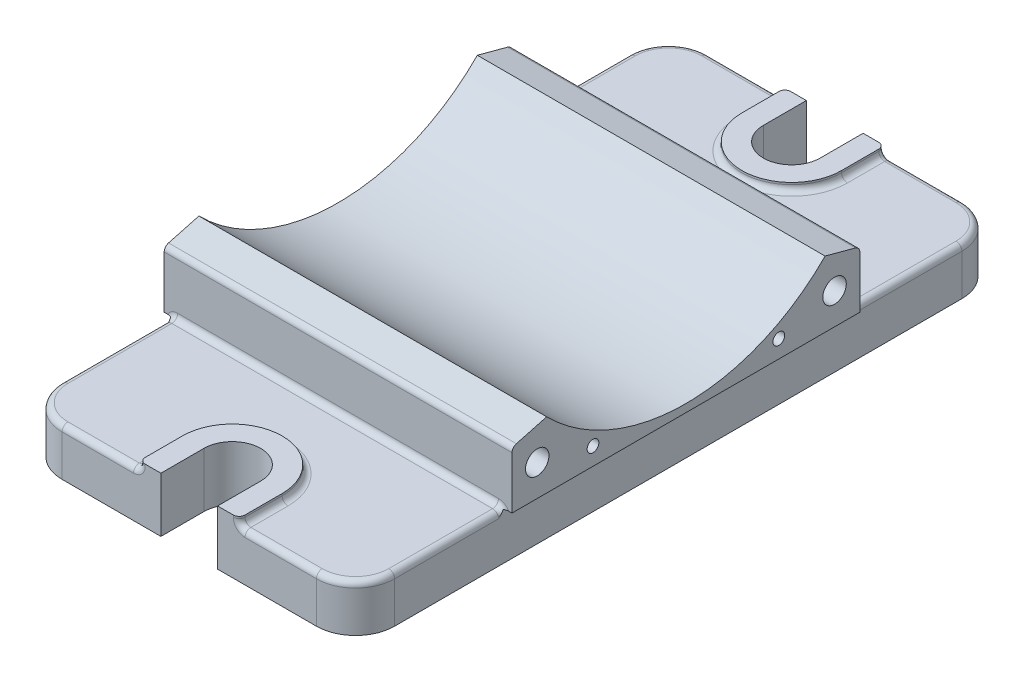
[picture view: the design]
ISO-10303-21;
HEADER;
FILE_DESCRIPTION(('STEP AP214'),'2;1');
FILE_NAME('part.step','',(''),(''),'','','');
FILE_SCHEMA(('AUTOMOTIVE_DESIGN { 1 0 10303 214 1 1 1 1 }'));
ENDSEC;
DATA;
#1=APPLICATION_CONTEXT('core data for automotive mechanical design processes');
#2=APPLICATION_PROTOCOL_DEFINITION('international standard','automotive_design',2000,#1);
#3=PRODUCT_CONTEXT('',#1,'mechanical');
#4=PRODUCT('Part','Part','',(#3));
#5=PRODUCT_RELATED_PRODUCT_CATEGORY('part','',(#4));
#6=PRODUCT_DEFINITION_FORMATION('','',#4);
#7=PRODUCT_DEFINITION_CONTEXT('part definition',#1,'design');
#8=PRODUCT_DEFINITION('design','',#6,#7);
#9=PRODUCT_DEFINITION_SHAPE('','',#8);
#10=(LENGTH_UNIT() NAMED_UNIT(*) SI_UNIT(.MILLI.,.METRE.));
#11=(NAMED_UNIT(*) PLANE_ANGLE_UNIT() SI_UNIT($,.RADIAN.));
#12=(NAMED_UNIT(*) SI_UNIT($,.STERADIAN.) SOLID_ANGLE_UNIT());
#13=UNCERTAINTY_MEASURE_WITH_UNIT(LENGTH_MEASURE(1.E-05),#10,'distance_accuracy_value','');
#14=(GEOMETRIC_REPRESENTATION_CONTEXT(3) GLOBAL_UNCERTAINTY_ASSIGNED_CONTEXT((#13)) GLOBAL_UNIT_ASSIGNED_CONTEXT((#10,
#11,#12)) REPRESENTATION_CONTEXT('',''));
#15=CARTESIAN_POINT('',(0.,0.,0.));
#16=DIRECTION('',(0.,0.,1.));
#17=DIRECTION('',(1.,0.,0.));
#18=AXIS2_PLACEMENT_3D('',#15,#16,#17);
#19=CARTESIAN_POINT('',(-44.45,64.,0.));
#20=DIRECTION('',(1.,0.,0.));
#21=DIRECTION('',(0.,0.,-1.));
#22=AXIS2_PLACEMENT_3D('',#19,#20,#21);
#23=PLANE('',#22);
#24=DIRECTION('',(0.,0.258819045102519,0.965925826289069));
#25=VECTOR('',#24,1.);
#26=CARTESIAN_POINT('',(-44.45,26.5,-44.45));
#27=LINE('',#26,#25);
#28=CARTESIAN_POINT('',(-44.45,26.7978982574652,-43.3382285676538));
#29=VERTEX_POINT('',#28);
#30=CARTESIAN_POINT('',(-44.45,28.8754645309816,-35.584645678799));
#31=VERTEX_POINT('',#30);
#32=EDGE_CURVE('E562',#29,#31,#27,.T.);
#33=ORIENTED_EDGE('',*,*,#32,.F.);
#34=CARTESIAN_POINT('',(-44.45,25.3490095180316,-42.95));
#35=DIRECTION('',(1.,0.,0.));
#36=DIRECTION('',(0.,0.,-1.));
#37=AXIS2_PLACEMENT_3D('',#34,#35,#36);
#38=CIRCLE('',#37,1.5);
#39=CARTESIAN_POINT('',(-44.45,25.3490095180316,-44.45));
#40=VERTEX_POINT('',#39);
#41=EDGE_CURVE('E737',#29,#40,#38,.F.);
#42=ORIENTED_EDGE('',*,*,#41,.T.);
#43=DIRECTION('',(0.,1.,0.));
#44=VECTOR('',#43,1.);
#45=CARTESIAN_POINT('',(-44.45,12.,-44.45));
#46=LINE('',#45,#44);
#47=CARTESIAN_POINT('',(-44.45,12.,-44.45));
#48=VERTEX_POINT('',#47);
#49=EDGE_CURVE('E559',#48,#40,#46,.T.);
#50=ORIENTED_EDGE('',*,*,#49,.F.);
#51=DIRECTION('',(0.,0.,-1.));
#52=VECTOR('',#51,1.);
#53=CARTESIAN_POINT('',(-44.45,12.,44.45));
#54=LINE('',#53,#52);
#55=CARTESIAN_POINT('',(-44.45,12.,44.45));
#56=VERTEX_POINT('',#55);
#57=EDGE_CURVE('E556',#56,#48,#54,.T.);
#58=ORIENTED_EDGE('',*,*,#57,.F.);
#59=DIRECTION('',(0.,-1.,0.));
#60=VECTOR('',#59,1.);
#61=CARTESIAN_POINT('',(-44.45,12.,44.45));
#62=LINE('',#61,#60);
#63=CARTESIAN_POINT('',(-44.45,25.3490095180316,44.45));
#64=VERTEX_POINT('',#63);
#65=EDGE_CURVE('E531',#64,#56,#62,.T.);
#66=ORIENTED_EDGE('',*,*,#65,.F.);
#67=CARTESIAN_POINT('',(-44.45,25.3490095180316,42.95));
#68=DIRECTION('',(1.,0.,0.));
#69=DIRECTION('',(0.,0.,-1.));
#70=AXIS2_PLACEMENT_3D('',#67,#68,#69);
#71=CIRCLE('',#70,1.5);
#72=CARTESIAN_POINT('',(-44.45,26.7978982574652,43.3382285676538));
#73=VERTEX_POINT('',#72);
#74=EDGE_CURVE('E735',#64,#73,#71,.F.);
#75=ORIENTED_EDGE('',*,*,#74,.T.);
#76=DIRECTION('',(0.,-0.258819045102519,0.965925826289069));
#77=VECTOR('',#76,1.);
#78=CARTESIAN_POINT('',(-44.45,26.5,44.45));
#79=LINE('',#78,#77);
#80=CARTESIAN_POINT('',(-44.45,28.8754645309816,35.584645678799));
#81=VERTEX_POINT('',#80);
#82=EDGE_CURVE('E541',#81,#73,#79,.T.);
#83=ORIENTED_EDGE('',*,*,#82,.F.);
#84=CARTESIAN_POINT('',(-44.45,64.,0.));
#85=DIRECTION('',(-1.,0.,0.));
#86=DIRECTION('',(0.,0.,-1.));
#87=AXIS2_PLACEMENT_3D('',#84,#85,#86);
#88=CIRCLE('',#87,50.);
#89=EDGE_CURVE('E564',#31,#81,#88,.T.);
#90=ORIENTED_EDGE('',*,*,#89,.F.);
#91=EDGE_LOOP('',(#33,#42,#50,#58,#66,#75,#83,#90));
#92=FACE_BOUND('',#91,.T.);
#93=CARTESIAN_POINT('',(-44.45,20.,-38.));
#94=DIRECTION('',(-1.,0.,0.));
#95=DIRECTION('',(0.,0.,1.));
#96=AXIS2_PLACEMENT_3D('',#93,#94,#95);
#97=CIRCLE('',#96,3.);
#98=CARTESIAN_POINT('',(-44.45,20.,-35.));
#99=VERTEX_POINT('',#98);
#100=EDGE_CURVE('E415',#99,#99,#97,.T.);
#101=ORIENTED_EDGE('',*,*,#100,.F.);
#102=EDGE_LOOP('',(#101));
#103=FACE_BOUND('',#102,.T.);
#104=CARTESIAN_POINT('',(-44.45,20.,38.));
#105=DIRECTION('',(-1.,0.,0.));
#106=DIRECTION('',(0.,0.,1.));
#107=AXIS2_PLACEMENT_3D('',#104,#105,#106);
#108=CIRCLE('',#107,3.);
#109=CARTESIAN_POINT('',(-44.45,20.,41.));
#110=VERTEX_POINT('',#109);
#111=EDGE_CURVE('E416',#110,#110,#108,.T.);
#112=ORIENTED_EDGE('',*,*,#111,.F.);
#113=EDGE_LOOP('',(#112));
#114=FACE_BOUND('',#113,.T.);
#115=CARTESIAN_POINT('',(-44.45,16.5,-23.75));
#116=DIRECTION('',(-1.,0.,0.));
#117=DIRECTION('',(0.,0.,1.));
#118=AXIS2_PLACEMENT_3D('',#115,#116,#117);
#119=CIRCLE('',#118,1.5);
#120=CARTESIAN_POINT('',(-44.45,16.5,-22.25));
#121=VERTEX_POINT('',#120);
#122=EDGE_CURVE('E1127',#121,#121,#119,.T.);
#123=ORIENTED_EDGE('',*,*,#122,.F.);
#124=EDGE_LOOP('',(#123));
#125=FACE_BOUND('',#124,.T.);
#126=CARTESIAN_POINT('',(-44.45,16.5,23.75));
#127=DIRECTION('',(1.,0.,0.));
#128=DIRECTION('',(0.,0.,-1.));
#129=AXIS2_PLACEMENT_3D('',#126,#127,#128);
#130=CIRCLE('',#129,1.5);
#131=CARTESIAN_POINT('',(-44.45,16.5,25.25));
#132=VERTEX_POINT('',#131);
#133=EDGE_CURVE('E1128',#132,#132,#130,.T.);
#134=ORIENTED_EDGE('',*,*,#133,.T.);
#135=EDGE_LOOP('',(#134));
#136=FACE_BOUND('',#135,.T.);
#137=ADVANCED_FACE('F40',(#92,#103,#114,#125,#136),#23,.F.);
#138=CARTESIAN_POINT('',(44.45,64.,0.));
#139=DIRECTION('',(1.,0.,0.));
#140=DIRECTION('',(0.,0.,-1.));
#141=AXIS2_PLACEMENT_3D('',#138,#139,#140);
#142=PLANE('',#141);
#143=DIRECTION('',(0.,1.,0.));
#144=VECTOR('',#143,1.);
#145=CARTESIAN_POINT('',(44.45,12.,-44.45));
#146=LINE('',#145,#144);
#147=CARTESIAN_POINT('',(44.45,12.,-44.45));
#148=VERTEX_POINT('',#147);
#149=CARTESIAN_POINT('',(44.45,25.3490095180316,-44.45));
#150=VERTEX_POINT('',#149);
#151=EDGE_CURVE('E543',#148,#150,#146,.T.);
#152=ORIENTED_EDGE('',*,*,#151,.T.);
#153=CARTESIAN_POINT('',(44.45,25.3490095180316,-42.95));
#154=DIRECTION('',(1.,0.,0.));
#155=DIRECTION('',(0.,0.,-1.));
#156=AXIS2_PLACEMENT_3D('',#153,#154,#155);
#157=CIRCLE('',#156,1.5);
#158=CARTESIAN_POINT('',(44.45,26.7978982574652,-43.3382285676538));
#159=VERTEX_POINT('',#158);
#160=EDGE_CURVE('E743',#150,#159,#157,.T.);
#161=ORIENTED_EDGE('',*,*,#160,.T.);
#162=DIRECTION('',(0.,0.258819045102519,0.965925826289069));
#163=VECTOR('',#162,1.);
#164=CARTESIAN_POINT('',(44.45,26.5,-44.45));
#165=LINE('',#164,#163);
#166=CARTESIAN_POINT('',(44.45,28.8754645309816,-35.584645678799));
#167=VERTEX_POINT('',#166);
#168=EDGE_CURVE('E546',#159,#167,#165,.T.);
#169=ORIENTED_EDGE('',*,*,#168,.T.);
#170=CARTESIAN_POINT('',(44.45,64.,0.));
#171=DIRECTION('',(-1.,0.,0.));
#172=DIRECTION('',(0.,0.,-1.));
#173=AXIS2_PLACEMENT_3D('',#170,#171,#172);
#174=CIRCLE('',#173,50.);
#175=CARTESIAN_POINT('',(44.45,28.8754645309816,35.584645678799));
#176=VERTEX_POINT('',#175);
#177=EDGE_CURVE('E548',#167,#176,#174,.T.);
#178=ORIENTED_EDGE('',*,*,#177,.T.);
#179=DIRECTION('',(0.,-0.258819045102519,0.965925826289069));
#180=VECTOR('',#179,1.);
#181=CARTESIAN_POINT('',(44.45,26.5,44.45));
#182=LINE('',#181,#180);
#183=CARTESIAN_POINT('',(44.45,26.7978982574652,43.3382285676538));
#184=VERTEX_POINT('',#183);
#185=EDGE_CURVE('E550',#176,#184,#182,.T.);
#186=ORIENTED_EDGE('',*,*,#185,.T.);
#187=CARTESIAN_POINT('',(44.45,25.3490095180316,42.95));
#188=DIRECTION('',(1.,0.,0.));
#189=DIRECTION('',(0.,0.,-1.));
#190=AXIS2_PLACEMENT_3D('',#187,#188,#189);
#191=CIRCLE('',#190,1.5);
#192=CARTESIAN_POINT('',(44.45,25.3490095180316,44.45));
#193=VERTEX_POINT('',#192);
#194=EDGE_CURVE('E741',#184,#193,#191,.T.);
#195=ORIENTED_EDGE('',*,*,#194,.T.);
#196=DIRECTION('',(0.,-1.,0.));
#197=VECTOR('',#196,1.);
#198=CARTESIAN_POINT('',(44.45,12.,44.45));
#199=LINE('',#198,#197);
#200=CARTESIAN_POINT('',(44.45,12.,44.45));
#201=VERTEX_POINT('',#200);
#202=EDGE_CURVE('E538',#193,#201,#199,.T.);
#203=ORIENTED_EDGE('',*,*,#202,.T.);
#204=DIRECTION('',(0.,0.,-1.));
#205=VECTOR('',#204,1.);
#206=CARTESIAN_POINT('',(44.45,12.,44.45));
#207=LINE('',#206,#205);
#208=EDGE_CURVE('E540',#201,#148,#207,.T.);
#209=ORIENTED_EDGE('',*,*,#208,.T.);
#210=EDGE_LOOP('',(#152,#161,#169,#178,#186,#195,#203,#209));
#211=FACE_BOUND('',#210,.T.);
#212=CARTESIAN_POINT('',(44.45,20.,38.));
#213=DIRECTION('',(1.,0.,0.));
#214=DIRECTION('',(0.,0.,-1.));
#215=AXIS2_PLACEMENT_3D('',#212,#213,#214);
#216=CIRCLE('',#215,3.);
#217=CARTESIAN_POINT('',(44.45,20.,35.));
#218=VERTEX_POINT('',#217);
#219=EDGE_CURVE('E440',#218,#218,#216,.T.);
#220=ORIENTED_EDGE('',*,*,#219,.F.);
#221=EDGE_LOOP('',(#220));
#222=FACE_BOUND('',#221,.T.);
#223=CARTESIAN_POINT('',(44.45,16.5,23.75));
#224=DIRECTION('',(1.,0.,0.));
#225=DIRECTION('',(0.,0.,-1.));
#226=AXIS2_PLACEMENT_3D('',#223,#224,#225);
#227=CIRCLE('',#226,1.5);
#228=CARTESIAN_POINT('',(44.45,16.5,22.25));
#229=VERTEX_POINT('',#228);
#230=EDGE_CURVE('E436',#229,#229,#227,.T.);
#231=ORIENTED_EDGE('',*,*,#230,.F.);
#232=EDGE_LOOP('',(#231));
#233=FACE_BOUND('',#232,.T.);
#234=CARTESIAN_POINT('',(44.45,20.,-38.));
#235=DIRECTION('',(1.,0.,0.));
#236=DIRECTION('',(0.,0.,-1.));
#237=AXIS2_PLACEMENT_3D('',#234,#235,#236);
#238=CIRCLE('',#237,3.);
#239=CARTESIAN_POINT('',(44.45,20.,-41.));
#240=VERTEX_POINT('',#239);
#241=EDGE_CURVE('E429',#240,#240,#238,.T.);
#242=ORIENTED_EDGE('',*,*,#241,.F.);
#243=EDGE_LOOP('',(#242));
#244=FACE_BOUND('',#243,.T.);
#245=CARTESIAN_POINT('',(44.45,16.5,-23.75));
#246=DIRECTION('',(-1.,0.,0.));
#247=DIRECTION('',(0.,0.,1.));
#248=AXIS2_PLACEMENT_3D('',#245,#246,#247);
#249=CIRCLE('',#248,1.5);
#250=CARTESIAN_POINT('',(44.45,16.5,-25.25));
#251=VERTEX_POINT('',#250);
#252=EDGE_CURVE('E1137',#251,#251,#249,.T.);
#253=ORIENTED_EDGE('',*,*,#252,.T.);
#254=EDGE_LOOP('',(#253));
#255=FACE_BOUND('',#254,.T.);
#256=ADVANCED_FACE('F975',(#211,#222,#233,#244,#255),#142,.T.);
#257=CARTESIAN_POINT('',(-42.5,12.,-82.5));
#258=DIRECTION('',(0.,0.,1.));
#259=DIRECTION('',(1.,0.,0.));
#260=AXIS2_PLACEMENT_3D('',#257,#258,#259);
#261=PLANE('',#260);
#262=CARTESIAN_POINT('',(-14.25,13.5,-82.5));
#263=DIRECTION('',(0.,0.,1.));
#264=DIRECTION('',(1.,0.,0.));
#265=AXIS2_PLACEMENT_3D('',#262,#263,#264);
#266=CIRCLE('',#265,3.);
#267=CARTESIAN_POINT('',(-11.25,13.5,-82.5));
#268=VERTEX_POINT('',#267);
#269=CARTESIAN_POINT('',(-14.25,10.5,-82.5));
#270=VERTEX_POINT('',#269);
#271=EDGE_CURVE('E628',#268,#270,#266,.F.);
#272=ORIENTED_EDGE('',*,*,#271,.F.);
#273=DIRECTION('',(0.,-1.,0.));
#274=VECTOR('',#273,1.);
#275=CARTESIAN_POINT('',(-11.25,14.,-82.5));
#276=LINE('',#275,#274);
#277=CARTESIAN_POINT('',(-11.25,14.,-82.5));
#278=VERTEX_POINT('',#277);
#279=EDGE_CURVE('E633',#268,#278,#276,.F.);
#280=ORIENTED_EDGE('',*,*,#279,.T.);
#281=DIRECTION('',(1.,0.,0.));
#282=VECTOR('',#281,1.);
#283=CARTESIAN_POINT('',(-12.75,14.,-82.5));
#284=LINE('',#283,#282);
#285=CARTESIAN_POINT('',(-7.24999999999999,14.,-82.5));
#286=VERTEX_POINT('',#285);
#287=EDGE_CURVE('E454',#278,#286,#284,.T.);
#288=ORIENTED_EDGE('',*,*,#287,.T.);
#289=DIRECTION('',(0.,1.,0.));
#290=VECTOR('',#289,1.);
#291=CARTESIAN_POINT('',(-7.24999999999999,-0.000999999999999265,-82.5));
#292=LINE('',#291,#290);
#293=CARTESIAN_POINT('',(-7.24999999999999,0.,-82.5));
#294=VERTEX_POINT('',#293);
#295=EDGE_CURVE('E483',#294,#286,#292,.T.);
#296=ORIENTED_EDGE('',*,*,#295,.F.);
#297=DIRECTION('',(-1.,0.,0.));
#298=VECTOR('',#297,1.);
#299=CARTESIAN_POINT('',(-42.5,0.,-82.5));
#300=LINE('',#299,#298);
#301=CARTESIAN_POINT('',(-32.5,0.,-82.5));
#302=VERTEX_POINT('',#301);
#303=EDGE_CURVE('E594',#294,#302,#300,.T.);
#304=ORIENTED_EDGE('',*,*,#303,.T.);
#305=DIRECTION('',(0.,-1.,0.));
#306=VECTOR('',#305,1.);
#307=CARTESIAN_POINT('',(-32.5,12.,-82.5));
#308=LINE('',#307,#306);
#309=CARTESIAN_POINT('',(-32.5,10.5,-82.5));
#310=VERTEX_POINT('',#309);
#311=EDGE_CURVE('E608',#302,#310,#308,.F.);
#312=ORIENTED_EDGE('',*,*,#311,.T.);
#313=DIRECTION('',(-1.,0.,0.));
#314=VECTOR('',#313,1.);
#315=CARTESIAN_POINT('',(-12.75,10.5,-82.5));
#316=LINE('',#315,#314);
#317=EDGE_CURVE('E631',#310,#270,#316,.F.);
#318=ORIENTED_EDGE('',*,*,#317,.T.);
#319=EDGE_LOOP('',(#272,#280,#288,#296,#304,#312,#318));
#320=FACE_BOUND('',#319,.T.);
#321=ADVANCED_FACE('F917',(#320),#261,.F.);
#322=DIRECTION('',(1.,0.,0.));
#323=VECTOR('',#322,1.);
#324=CARTESIAN_POINT('',(7.25000000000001,14.,-82.5));
#325=LINE('',#324,#323);
#326=CARTESIAN_POINT('',(7.25000000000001,14.,-82.5));
#327=VERTEX_POINT('',#326);
#328=CARTESIAN_POINT('',(11.25,14.,-82.5));
#329=VERTEX_POINT('',#328);
#330=EDGE_CURVE('E464',#327,#329,#325,.T.);
#331=ORIENTED_EDGE('',*,*,#330,.T.);
#332=DIRECTION('',(0.,-1.,0.));
#333=VECTOR('',#332,1.);
#334=CARTESIAN_POINT('',(11.25,12.,-82.5));
#335=LINE('',#334,#333);
#336=CARTESIAN_POINT('',(11.25,13.5,-82.5));
#337=VERTEX_POINT('',#336);
#338=EDGE_CURVE('E644',#329,#337,#335,.T.);
#339=ORIENTED_EDGE('',*,*,#338,.T.);
#340=CARTESIAN_POINT('',(14.25,13.5,-82.5));
#341=DIRECTION('',(0.,0.,1.));
#342=DIRECTION('',(1.,0.,0.));
#343=AXIS2_PLACEMENT_3D('',#340,#341,#342);
#344=CIRCLE('',#343,3.);
#345=CARTESIAN_POINT('',(14.25,10.5,-82.5));
#346=VERTEX_POINT('',#345);
#347=EDGE_CURVE('E641',#346,#337,#344,.F.);
#348=ORIENTED_EDGE('',*,*,#347,.F.);
#349=DIRECTION('',(-1.,0.,0.));
#350=VECTOR('',#349,1.);
#351=CARTESIAN_POINT('',(32.5,10.5,-82.5));
#352=LINE('',#351,#350);
#353=CARTESIAN_POINT('',(32.5,10.5,-82.5));
#354=VERTEX_POINT('',#353);
#355=EDGE_CURVE('E639',#346,#354,#352,.F.);
#356=ORIENTED_EDGE('',*,*,#355,.T.);
#357=DIRECTION('',(0.,-1.,0.));
#358=VECTOR('',#357,1.);
#359=CARTESIAN_POINT('',(32.5,12.,-82.5));
#360=LINE('',#359,#358);
#361=CARTESIAN_POINT('',(32.5,0.,-82.5));
#362=VERTEX_POINT('',#361);
#363=EDGE_CURVE('E611',#354,#362,#360,.T.);
#364=ORIENTED_EDGE('',*,*,#363,.T.);
#365=CARTESIAN_POINT('',(7.25000000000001,0.,-82.5));
#366=VERTEX_POINT('',#365);
#367=EDGE_CURVE('E583',#362,#366,#300,.T.);
#368=ORIENTED_EDGE('',*,*,#367,.T.);
#369=DIRECTION('',(0.,1.,0.));
#370=VECTOR('',#369,1.);
#371=CARTESIAN_POINT('',(7.25000000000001,-0.000999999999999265,-82.5));
#372=LINE('',#371,#370);
#373=EDGE_CURVE('E487',#366,#327,#372,.T.);
#374=ORIENTED_EDGE('',*,*,#373,.T.);
#375=EDGE_LOOP('',(#331,#339,#348,#356,#364,#368,#374));
#376=FACE_BOUND('',#375,.T.);
#377=ADVANCED_FACE('F1626',(#376),#261,.F.);
#378=CARTESIAN_POINT('',(0.,12.,0.));
#379=DIRECTION('',(0.,1.,0.));
#380=DIRECTION('',(0.,0.,1.));
#381=AXIS2_PLACEMENT_3D('',#378,#379,#380);
#382=PLANE('',#381);
#383=DIRECTION('',(0.,0.,1.));
#384=VECTOR('',#383,1.);
#385=CARTESIAN_POINT('',(-41.,12.,-44.45));
#386=LINE('',#385,#384);
#387=CARTESIAN_POINT('',(-41.,12.,-72.5));
#388=VERTEX_POINT('',#387);
#389=CARTESIAN_POINT('',(-41.,12.,-45.95));
#390=VERTEX_POINT('',#389);
#391=EDGE_CURVE('E693',#388,#390,#386,.T.);
#392=ORIENTED_EDGE('',*,*,#391,.T.);
#393=DIRECTION('',(-1.,0.,0.));
#394=VECTOR('',#393,1.);
#395=CARTESIAN_POINT('',(0.,12.,-45.95));
#396=LINE('',#395,#394);
#397=CARTESIAN_POINT('',(41.,12.,-45.95));
#398=VERTEX_POINT('',#397);
#399=EDGE_CURVE('E849',#390,#398,#396,.F.);
#400=ORIENTED_EDGE('',*,*,#399,.T.);
#401=DIRECTION('',(0.,0.,-1.));
#402=VECTOR('',#401,1.);
#403=CARTESIAN_POINT('',(41.,12.,-72.5));
#404=LINE('',#403,#402);
#405=CARTESIAN_POINT('',(41.,12.,-72.5));
#406=VERTEX_POINT('',#405);
#407=EDGE_CURVE('E677',#398,#406,#404,.T.);
#408=ORIENTED_EDGE('',*,*,#407,.T.);
#409=CARTESIAN_POINT('',(32.5,12.,-72.5));
#410=DIRECTION('',(0.,1.,0.));
#411=DIRECTION('',(0.,0.,1.));
#412=AXIS2_PLACEMENT_3D('',#409,#410,#411);
#413=CIRCLE('',#412,8.5);
#414=CARTESIAN_POINT('',(32.5,12.,-81.));
#415=VERTEX_POINT('',#414);
#416=EDGE_CURVE('E679',#406,#415,#413,.T.);
#417=ORIENTED_EDGE('',*,*,#416,.T.);
#418=DIRECTION('',(-1.,0.,0.));
#419=VECTOR('',#418,1.);
#420=CARTESIAN_POINT('',(12.75,12.,-81.));
#421=LINE('',#420,#419);
#422=CARTESIAN_POINT('',(14.25,12.,-81.));
#423=VERTEX_POINT('',#422);
#424=EDGE_CURVE('E681',#415,#423,#421,.T.);
#425=ORIENTED_EDGE('',*,*,#424,.T.);
#426=DIRECTION('',(0.,0.,1.));
#427=VECTOR('',#426,1.);
#428=CARTESIAN_POINT('',(14.25,12.,-71.5));
#429=LINE('',#428,#427);
#430=CARTESIAN_POINT('',(14.25,12.,-71.5));
#431=VERTEX_POINT('',#430);
#432=EDGE_CURVE('E683',#423,#431,#429,.T.);
#433=ORIENTED_EDGE('',*,*,#432,.T.);
#434=CARTESIAN_POINT('',(0.,12.,-71.5));
#435=DIRECTION('',(0.,1.,0.));
#436=DIRECTION('',(0.,0.,1.));
#437=AXIS2_PLACEMENT_3D('',#434,#435,#436);
#438=CIRCLE('',#437,14.25);
#439=CARTESIAN_POINT('',(-14.25,12.,-71.5));
#440=VERTEX_POINT('',#439);
#441=EDGE_CURVE('E685',#431,#440,#438,.F.);
#442=ORIENTED_EDGE('',*,*,#441,.T.);
#443=DIRECTION('',(0.,0.,-1.));
#444=VECTOR('',#443,1.);
#445=CARTESIAN_POINT('',(-14.25,12.,-82.5));
#446=LINE('',#445,#444);
#447=CARTESIAN_POINT('',(-14.25,12.,-81.));
#448=VERTEX_POINT('',#447);
#449=EDGE_CURVE('E687',#440,#448,#446,.T.);
#450=ORIENTED_EDGE('',*,*,#449,.T.);
#451=DIRECTION('',(-1.,0.,0.));
#452=VECTOR('',#451,1.);
#453=CARTESIAN_POINT('',(-32.5,12.,-81.));
#454=LINE('',#453,#452);
#455=CARTESIAN_POINT('',(-32.5,12.,-81.));
#456=VERTEX_POINT('',#455);
#457=EDGE_CURVE('E689',#448,#456,#454,.T.);
#458=ORIENTED_EDGE('',*,*,#457,.T.);
#459=CARTESIAN_POINT('',(-32.5,12.,-72.5));
#460=DIRECTION('',(0.,1.,0.));
#461=DIRECTION('',(0.,0.,1.));
#462=AXIS2_PLACEMENT_3D('',#459,#460,#461);
#463=CIRCLE('',#462,8.5);
#464=EDGE_CURVE('E691',#456,#388,#463,.T.);
#465=ORIENTED_EDGE('',*,*,#464,.T.);
#466=EDGE_LOOP('',(#392,#400,#408,#417,#425,#433,#442,#450,#458,#465));
#467=FACE_BOUND('',#466,.T.);
#468=ADVANCED_FACE('F1614',(#467),#382,.T.);
#469=CARTESIAN_POINT('',(0.,0.,0.));
#470=DIRECTION('',(0.,1.,0.));
#471=DIRECTION('',(0.,0.,1.));
#472=AXIS2_PLACEMENT_3D('',#469,#470,#471);
#473=PLANE('',#472);
#474=DIRECTION('',(0.,0.,1.));
#475=VECTOR('',#474,1.);
#476=CARTESIAN_POINT('',(-42.5,0.,-82.5));
#477=LINE('',#476,#475);
#478=CARTESIAN_POINT('',(-42.5,0.,-72.5));
#479=VERTEX_POINT('',#478);
#480=CARTESIAN_POINT('',(-42.5,0.,72.5));
#481=VERTEX_POINT('',#480);
#482=EDGE_CURVE('E581',#479,#481,#477,.T.);
#483=ORIENTED_EDGE('',*,*,#482,.F.);
#484=CARTESIAN_POINT('',(-32.5,0.,-72.5));
#485=DIRECTION('',(0.,1.,0.));
#486=DIRECTION('',(0.,0.,1.));
#487=AXIS2_PLACEMENT_3D('',#484,#485,#486);
#488=CIRCLE('',#487,10.);
#489=EDGE_CURVE('E606',#479,#302,#488,.F.);
#490=ORIENTED_EDGE('',*,*,#489,.T.);
#491=ORIENTED_EDGE('',*,*,#303,.F.);
#492=DIRECTION('',(0.,0.,1.));
#493=VECTOR('',#492,1.);
#494=CARTESIAN_POINT('',(-7.24999999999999,0.,-82.5));
#495=LINE('',#494,#493);
#496=CARTESIAN_POINT('',(-7.25,0.,-71.5));
#497=VERTEX_POINT('',#496);
#498=EDGE_CURVE('E479',#294,#497,#495,.T.);
#499=ORIENTED_EDGE('',*,*,#498,.T.);
#500=CARTESIAN_POINT('',(0.,0.,-71.5));
#501=DIRECTION('',(0.,1.,0.));
#502=DIRECTION('',(0.,0.,1.));
#503=AXIS2_PLACEMENT_3D('',#500,#501,#502);
#504=CIRCLE('',#503,7.25);
#505=CARTESIAN_POINT('',(7.25,0.,-71.5));
#506=VERTEX_POINT('',#505);
#507=EDGE_CURVE('E486',#497,#506,#504,.T.);
#508=ORIENTED_EDGE('',*,*,#507,.T.);
#509=DIRECTION('',(0.,0.,-1.));
#510=VECTOR('',#509,1.);
#511=CARTESIAN_POINT('',(7.25000000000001,0.,-82.5));
#512=LINE('',#511,#510);
#513=EDGE_CURVE('E476',#506,#366,#512,.T.);
#514=ORIENTED_EDGE('',*,*,#513,.T.);
#515=ORIENTED_EDGE('',*,*,#367,.F.);
#516=CARTESIAN_POINT('',(32.5,0.,-72.5));
#517=DIRECTION('',(0.,1.,0.));
#518=DIRECTION('',(0.,0.,1.));
#519=AXIS2_PLACEMENT_3D('',#516,#517,#518);
#520=CIRCLE('',#519,10.);
#521=CARTESIAN_POINT('',(42.5,0.,-72.5));
#522=VERTEX_POINT('',#521);
#523=EDGE_CURVE('E604',#362,#522,#520,.F.);
#524=ORIENTED_EDGE('',*,*,#523,.T.);
#525=DIRECTION('',(0.,0.,-1.));
#526=VECTOR('',#525,1.);
#527=CARTESIAN_POINT('',(42.5,0.,-82.5));
#528=LINE('',#527,#526);
#529=CARTESIAN_POINT('',(42.5,0.,72.5));
#530=VERTEX_POINT('',#529);
#531=EDGE_CURVE('E591',#530,#522,#528,.T.);
#532=ORIENTED_EDGE('',*,*,#531,.F.);
#533=CARTESIAN_POINT('',(32.5,0.,72.5));
#534=DIRECTION('',(0.,1.,0.));
#535=DIRECTION('',(0.,0.,1.));
#536=AXIS2_PLACEMENT_3D('',#533,#534,#535);
#537=CIRCLE('',#536,10.);
#538=CARTESIAN_POINT('',(32.5,0.,82.5));
#539=VERTEX_POINT('',#538);
#540=EDGE_CURVE('E602',#530,#539,#537,.F.);
#541=ORIENTED_EDGE('',*,*,#540,.T.);
#542=DIRECTION('',(1.,0.,0.));
#543=VECTOR('',#542,1.);
#544=CARTESIAN_POINT('',(-42.5,0.,82.5));
#545=LINE('',#544,#543);
#546=CARTESIAN_POINT('',(7.25000000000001,0.,82.5));
#547=VERTEX_POINT('',#546);
#548=EDGE_CURVE('E588',#547,#539,#545,.T.);
#549=ORIENTED_EDGE('',*,*,#548,.F.);
#550=DIRECTION('',(0.,0.,1.));
#551=VECTOR('',#550,1.);
#552=CARTESIAN_POINT('',(7.25000000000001,0.,82.5));
#553=LINE('',#552,#551);
#554=CARTESIAN_POINT('',(7.25000000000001,0.,71.5));
#555=VERTEX_POINT('',#554);
#556=EDGE_CURVE('E521',#555,#547,#553,.T.);
#557=ORIENTED_EDGE('',*,*,#556,.F.);
#558=CARTESIAN_POINT('',(0.,0.,71.5));
#559=DIRECTION('',(0.,1.,0.));
#560=DIRECTION('',(0.,0.,1.));
#561=AXIS2_PLACEMENT_3D('',#558,#559,#560);
#562=CIRCLE('',#561,7.25);
#563=CARTESIAN_POINT('',(-7.25,0.,71.5));
#564=VERTEX_POINT('',#563);
#565=EDGE_CURVE('E523',#564,#555,#562,.F.);
#566=ORIENTED_EDGE('',*,*,#565,.F.);
#567=DIRECTION('',(0.,0.,-1.));
#568=VECTOR('',#567,1.);
#569=CARTESIAN_POINT('',(-7.24999999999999,0.,82.5));
#570=LINE('',#569,#568);
#571=CARTESIAN_POINT('',(-7.24999999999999,0.,82.5));
#572=VERTEX_POINT('',#571);
#573=EDGE_CURVE('E525',#572,#564,#570,.T.);
#574=ORIENTED_EDGE('',*,*,#573,.F.);
#575=CARTESIAN_POINT('',(-32.5,0.,82.5));
#576=VERTEX_POINT('',#575);
#577=EDGE_CURVE('E589',#576,#572,#545,.T.);
#578=ORIENTED_EDGE('',*,*,#577,.F.);
#579=CARTESIAN_POINT('',(-32.5,0.,72.5));
#580=DIRECTION('',(0.,1.,0.));
#581=DIRECTION('',(0.,0.,1.));
#582=AXIS2_PLACEMENT_3D('',#579,#580,#581);
#583=CIRCLE('',#582,10.);
#584=EDGE_CURVE('E600',#576,#481,#583,.F.);
#585=ORIENTED_EDGE('',*,*,#584,.T.);
#586=EDGE_LOOP('',(#483,#490,#491,#499,#508,#514,#515,#524,#532,#541,#549,#557,#566,#574,#578,#585));
#587=FACE_BOUND('',#586,.T.);
#588=ADVANCED_FACE('F1611',(#587),#473,.F.);
#589=DIRECTION('',(0.,0.,-1.));
#590=VECTOR('',#589,1.);
#591=CARTESIAN_POINT('',(41.,12.,44.45));
#592=LINE('',#591,#590);
#593=CARTESIAN_POINT('',(41.,12.,72.5));
#594=VERTEX_POINT('',#593);
#595=CARTESIAN_POINT('',(41.,12.,45.95));
#596=VERTEX_POINT('',#595);
#597=EDGE_CURVE('E707',#594,#596,#592,.T.);
#598=ORIENTED_EDGE('',*,*,#597,.T.);
#599=DIRECTION('',(-1.,0.,0.));
#600=VECTOR('',#599,1.);
#601=CARTESIAN_POINT('',(0.,12.,45.95));
#602=LINE('',#601,#600);
#603=CARTESIAN_POINT('',(-41.,12.,45.95));
#604=VERTEX_POINT('',#603);
#605=EDGE_CURVE('E847',#596,#604,#602,.T.);
#606=ORIENTED_EDGE('',*,*,#605,.T.);
#607=DIRECTION('',(0.,0.,1.));
#608=VECTOR('',#607,1.);
#609=CARTESIAN_POINT('',(-41.,12.,72.5));
#610=LINE('',#609,#608);
#611=CARTESIAN_POINT('',(-41.,12.,72.5));
#612=VERTEX_POINT('',#611);
#613=EDGE_CURVE('E724',#604,#612,#610,.T.);
#614=ORIENTED_EDGE('',*,*,#613,.T.);
#615=CARTESIAN_POINT('',(-32.5,12.,72.5));
#616=DIRECTION('',(0.,1.,0.));
#617=DIRECTION('',(0.,0.,1.));
#618=AXIS2_PLACEMENT_3D('',#615,#616,#617);
#619=CIRCLE('',#618,8.5);
#620=CARTESIAN_POINT('',(-32.5,12.,81.));
#621=VERTEX_POINT('',#620);
#622=EDGE_CURVE('E722',#612,#621,#619,.T.);
#623=ORIENTED_EDGE('',*,*,#622,.T.);
#624=DIRECTION('',(1.,0.,0.));
#625=VECTOR('',#624,1.);
#626=CARTESIAN_POINT('',(-12.75,12.,81.));
#627=LINE('',#626,#625);
#628=CARTESIAN_POINT('',(-14.25,12.,81.));
#629=VERTEX_POINT('',#628);
#630=EDGE_CURVE('E720',#621,#629,#627,.T.);
#631=ORIENTED_EDGE('',*,*,#630,.T.);
#632=DIRECTION('',(0.,0.,1.));
#633=VECTOR('',#632,1.);
#634=CARTESIAN_POINT('',(-14.25,12.,0.));
#635=LINE('',#634,#633);
#636=CARTESIAN_POINT('',(-14.25,12.,71.5));
#637=VERTEX_POINT('',#636);
#638=EDGE_CURVE('E718',#629,#637,#635,.F.);
#639=ORIENTED_EDGE('',*,*,#638,.T.);
#640=CARTESIAN_POINT('',(0.,12.,71.5));
#641=DIRECTION('',(0.,1.,0.));
#642=DIRECTION('',(0.,0.,1.));
#643=AXIS2_PLACEMENT_3D('',#640,#641,#642);
#644=CIRCLE('',#643,14.25);
#645=CARTESIAN_POINT('',(14.25,12.,71.5));
#646=VERTEX_POINT('',#645);
#647=EDGE_CURVE('E716',#637,#646,#644,.F.);
#648=ORIENTED_EDGE('',*,*,#647,.T.);
#649=DIRECTION('',(0.,0.,-1.));
#650=VECTOR('',#649,1.);
#651=CARTESIAN_POINT('',(14.25,12.,0.));
#652=LINE('',#651,#650);
#653=CARTESIAN_POINT('',(14.25,12.,81.));
#654=VERTEX_POINT('',#653);
#655=EDGE_CURVE('E714',#646,#654,#652,.F.);
#656=ORIENTED_EDGE('',*,*,#655,.T.);
#657=DIRECTION('',(1.,0.,0.));
#658=VECTOR('',#657,1.);
#659=CARTESIAN_POINT('',(32.5,12.,81.));
#660=LINE('',#659,#658);
#661=CARTESIAN_POINT('',(32.5,12.,81.));
#662=VERTEX_POINT('',#661);
#663=EDGE_CURVE('E712',#654,#662,#660,.T.);
#664=ORIENTED_EDGE('',*,*,#663,.T.);
#665=CARTESIAN_POINT('',(32.5,12.,72.5));
#666=DIRECTION('',(0.,1.,0.));
#667=DIRECTION('',(0.,0.,1.));
#668=AXIS2_PLACEMENT_3D('',#665,#666,#667);
#669=CIRCLE('',#668,8.5);
#670=EDGE_CURVE('E710',#662,#594,#669,.T.);
#671=ORIENTED_EDGE('',*,*,#670,.T.);
#672=EDGE_LOOP('',(#598,#606,#614,#623,#631,#639,#648,#656,#664,#671));
#673=FACE_BOUND('',#672,.T.);
#674=ADVANCED_FACE('F1604',(#673),#382,.T.);
#675=CARTESIAN_POINT('',(-42.5,12.,82.5));
#676=DIRECTION('',(0.,0.,-1.));
#677=DIRECTION('',(-1.,0.,0.));
#678=AXIS2_PLACEMENT_3D('',#675,#676,#677);
#679=PLANE('',#678);
#680=DIRECTION('',(1.,0.,0.));
#681=VECTOR('',#680,1.);
#682=CARTESIAN_POINT('',(-12.75,14.,82.5));
#683=LINE('',#682,#681);
#684=CARTESIAN_POINT('',(-11.25,14.,82.5));
#685=VERTEX_POINT('',#684);
#686=CARTESIAN_POINT('',(-7.24999999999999,14.,82.5));
#687=VERTEX_POINT('',#686);
#688=EDGE_CURVE('E510',#685,#687,#683,.T.);
#689=ORIENTED_EDGE('',*,*,#688,.F.);
#690=DIRECTION('',(0.,-1.,0.));
#691=VECTOR('',#690,1.);
#692=CARTESIAN_POINT('',(-11.25,12.,82.5));
#693=LINE('',#692,#691);
#694=CARTESIAN_POINT('',(-11.25,13.5,82.5));
#695=VERTEX_POINT('',#694);
#696=EDGE_CURVE('E655',#685,#695,#693,.T.);
#697=ORIENTED_EDGE('',*,*,#696,.T.);
#698=CARTESIAN_POINT('',(-14.25,13.5,82.5));
#699=DIRECTION('',(0.,0.,-1.));
#700=DIRECTION('',(-1.,0.,0.));
#701=AXIS2_PLACEMENT_3D('',#698,#699,#700);
#702=CIRCLE('',#701,3.);
#703=CARTESIAN_POINT('',(-14.25,10.5,82.5));
#704=VERTEX_POINT('',#703);
#705=EDGE_CURVE('E652',#704,#695,#702,.F.);
#706=ORIENTED_EDGE('',*,*,#705,.F.);
#707=DIRECTION('',(1.,0.,0.));
#708=VECTOR('',#707,1.);
#709=CARTESIAN_POINT('',(-32.5,10.5,82.5));
#710=LINE('',#709,#708);
#711=CARTESIAN_POINT('',(-32.5,10.5,82.5));
#712=VERTEX_POINT('',#711);
#713=EDGE_CURVE('E650',#704,#712,#710,.F.);
#714=ORIENTED_EDGE('',*,*,#713,.T.);
#715=DIRECTION('',(0.,-1.,0.));
#716=VECTOR('',#715,1.);
#717=CARTESIAN_POINT('',(-32.5,12.,82.5));
#718=LINE('',#717,#716);
#719=EDGE_CURVE('E621',#712,#576,#718,.T.);
#720=ORIENTED_EDGE('',*,*,#719,.T.);
#721=ORIENTED_EDGE('',*,*,#577,.T.);
#722=DIRECTION('',(0.,1.,0.));
#723=VECTOR('',#722,1.);
#724=CARTESIAN_POINT('',(-7.24999999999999,-0.000999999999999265,82.5));
#725=LINE('',#724,#723);
#726=EDGE_CURVE('E528',#572,#687,#725,.T.);
#727=ORIENTED_EDGE('',*,*,#726,.T.);
#728=EDGE_LOOP('',(#689,#697,#706,#714,#720,#721,#727));
#729=FACE_BOUND('',#728,.T.);
#730=ADVANCED_FACE('F923',(#729),#679,.F.);
#731=CARTESIAN_POINT('',(-42.5,12.,-82.5));
#732=DIRECTION('',(1.,0.,0.));
#733=DIRECTION('',(0.,0.,-1.));
#734=AXIS2_PLACEMENT_3D('',#731,#732,#733);
#735=PLANE('',#734);
#736=DIRECTION('',(0.,0.,1.));
#737=VECTOR('',#736,1.);
#738=CARTESIAN_POINT('',(-42.5,12.,-82.5));
#739=LINE('',#738,#737);
#740=CARTESIAN_POINT('',(-42.5,12.,-44.7343018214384));
#741=VERTEX_POINT('',#740);
#742=CARTESIAN_POINT('',(-42.5,12.,44.7343018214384));
#743=VERTEX_POINT('',#742);
#744=EDGE_CURVE('E57',#741,#743,#739,.T.);
#745=ORIENTED_EDGE('',*,*,#744,.F.);
#746=CARTESIAN_POINT('',(-42.5,12.,-44.7343018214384));
#747=CARTESIAN_POINT('',(-42.5,11.805839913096,-44.833612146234));
#748=CARTESIAN_POINT('',(-42.5,11.6242150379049,-44.9519430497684));
#749=CARTESIAN_POINT('',(-42.5,11.2803304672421,-45.2117989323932));
#750=CARTESIAN_POINT('',(-42.5000000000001,11.1179206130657,-45.3531202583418));
#751=CARTESIAN_POINT('',(-42.5,10.8055770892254,-45.6445229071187));
#752=CARTESIAN_POINT('',(-42.4999999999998,10.6555193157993,-45.7944818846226));
#753=CARTESIAN_POINT('',(-42.5,10.5036514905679,-45.9463485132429));
#754=CARTESIAN_POINT('',(-42.5,10.501825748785,-45.9481742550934));
#755=CARTESIAN_POINT('',(-42.5,10.5,-45.95));
#756=B_SPLINE_CURVE_WITH_KNOTS('',3,(#746,#747,#748,#749,#750,#751,#752,#753,#754,#755),
.UNSPECIFIED.,.F.,.F.,(4,2,2,2,4),(0.,0.649606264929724,1.29374362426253,1.93031747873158,
1.93806344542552),.UNSPECIFIED.);
#757=CARTESIAN_POINT('',(-42.5,10.5,-45.95));
#758=VERTEX_POINT('',#757);
#759=EDGE_CURVE('E11',#741,#758,#756,.T.);
#760=ORIENTED_EDGE('',*,*,#759,.T.);
#761=DIRECTION('',(0.,0.,1.));
#762=VECTOR('',#761,1.);
#763=CARTESIAN_POINT('',(-42.5,10.5,-72.5));
#764=LINE('',#763,#762);
#765=CARTESIAN_POINT('',(-42.5,10.5,-72.5));
#766=VERTEX_POINT('',#765);
#767=EDGE_CURVE('E701',#758,#766,#764,.F.);
#768=ORIENTED_EDGE('',*,*,#767,.T.);
#769=DIRECTION('',(0.,-1.,0.));
#770=VECTOR('',#769,1.);
#771=CARTESIAN_POINT('',(-42.5,12.,-72.5));
#772=LINE('',#771,#770);
#773=EDGE_CURVE('E598',#766,#479,#772,.T.);
#774=ORIENTED_EDGE('',*,*,#773,.T.);
#775=ORIENTED_EDGE('',*,*,#482,.T.);
#776=DIRECTION('',(0.,-1.,0.));
#777=VECTOR('',#776,1.);
#778=CARTESIAN_POINT('',(-42.5,12.,72.5));
#779=LINE('',#778,#777);
#780=CARTESIAN_POINT('',(-42.5,10.5,72.5));
#781=VERTEX_POINT('',#780);
#782=EDGE_CURVE('E585',#481,#781,#779,.F.);
#783=ORIENTED_EDGE('',*,*,#782,.T.);
#784=DIRECTION('',(0.,0.,1.));
#785=VECTOR('',#784,1.);
#786=CARTESIAN_POINT('',(-42.5,10.5,44.45));
#787=LINE('',#786,#785);
#788=CARTESIAN_POINT('',(-42.5,10.5,45.95));
#789=VERTEX_POINT('',#788);
#790=EDGE_CURVE('E698',#781,#789,#787,.F.);
#791=ORIENTED_EDGE('',*,*,#790,.T.);
#792=CARTESIAN_POINT('',(-42.5,12.,44.7343018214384));
#793=CARTESIAN_POINT('',(-42.5,11.8058399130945,44.8336121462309));
#794=CARTESIAN_POINT('',(-42.5,11.6242150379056,44.9519430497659));
#795=CARTESIAN_POINT('',(-42.5,11.280330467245,45.211798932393));
#796=CARTESIAN_POINT('',(-42.5,11.117920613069,45.3531202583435));
#797=CARTESIAN_POINT('',(-42.5,10.805577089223,45.6445229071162));
#798=CARTESIAN_POINT('',(-42.5,10.6555193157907,45.794481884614));
#799=CARTESIAN_POINT('',(-42.5,10.5036514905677,45.9463485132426));
#800=CARTESIAN_POINT('',(-42.5,10.5018257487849,45.9481742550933));
#801=CARTESIAN_POINT('',(-42.5,10.5,45.95));
#802=B_SPLINE_CURVE_WITH_KNOTS('',3,(#792,#793,#794,#795,#796,#797,#798,#799,#800,#801),
.UNSPECIFIED.,.F.,.F.,(4,2,2,2,4),(0.,0.649606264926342,1.29374362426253,1.93031747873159,
1.93806344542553),.UNSPECIFIED.);
#803=EDGE_CURVE('E889',#789,#743,#802,.F.);
#804=ORIENTED_EDGE('',*,*,#803,.T.);
#805=EDGE_LOOP('',(#745,#760,#768,#774,#775,#783,#791,#804));
#806=FACE_BOUND('',#805,.T.);
#807=ADVANCED_FACE('F921',(#806),#735,.F.);
#808=CARTESIAN_POINT('',(14.25,13.5,82.5));
#809=DIRECTION('',(0.,0.,-1.));
#810=DIRECTION('',(-1.,0.,0.));
#811=AXIS2_PLACEMENT_3D('',#808,#809,#810);
#812=CIRCLE('',#811,3.);
#813=CARTESIAN_POINT('',(11.25,13.5,82.5));
#814=VERTEX_POINT('',#813);
#815=CARTESIAN_POINT('',(14.25,10.5,82.5));
#816=VERTEX_POINT('',#815);
#817=EDGE_CURVE('E670',#814,#816,#812,.F.);
#818=ORIENTED_EDGE('',*,*,#817,.F.);
#819=DIRECTION('',(0.,-1.,0.));
#820=VECTOR('',#819,1.);
#821=CARTESIAN_POINT('',(11.25,12.,82.5));
#822=LINE('',#821,#820);
#823=CARTESIAN_POINT('',(11.25,14.,82.5));
#824=VERTEX_POINT('',#823);
#825=EDGE_CURVE('E675',#814,#824,#822,.F.);
#826=ORIENTED_EDGE('',*,*,#825,.T.);
#827=DIRECTION('',(1.,0.,0.));
#828=VECTOR('',#827,1.);
#829=CARTESIAN_POINT('',(7.25000000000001,14.,82.5));
#830=LINE('',#829,#828);
#831=CARTESIAN_POINT('',(7.25000000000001,14.,82.5));
#832=VERTEX_POINT('',#831);
#833=EDGE_CURVE('E500',#832,#824,#830,.T.);
#834=ORIENTED_EDGE('',*,*,#833,.F.);
#835=DIRECTION('',(0.,1.,0.));
#836=VECTOR('',#835,1.);
#837=CARTESIAN_POINT('',(7.25000000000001,-0.000999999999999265,82.5));
#838=LINE('',#837,#836);
#839=EDGE_CURVE('E534',#547,#832,#838,.T.);
#840=ORIENTED_EDGE('',*,*,#839,.F.);
#841=ORIENTED_EDGE('',*,*,#548,.T.);
#842=DIRECTION('',(0.,-1.,0.));
#843=VECTOR('',#842,1.);
#844=CARTESIAN_POINT('',(32.5,12.,82.5));
#845=LINE('',#844,#843);
#846=CARTESIAN_POINT('',(32.5,10.5,82.5));
#847=VERTEX_POINT('',#846);
#848=EDGE_CURVE('E618',#539,#847,#845,.F.);
#849=ORIENTED_EDGE('',*,*,#848,.T.);
#850=DIRECTION('',(1.,0.,0.));
#851=VECTOR('',#850,1.);
#852=CARTESIAN_POINT('',(12.75,10.5,82.5));
#853=LINE('',#852,#851);
#854=EDGE_CURVE('E673',#847,#816,#853,.F.);
#855=ORIENTED_EDGE('',*,*,#854,.T.);
#856=EDGE_LOOP('',(#818,#826,#834,#840,#841,#849,#855));
#857=FACE_BOUND('',#856,.T.);
#858=ADVANCED_FACE('F915',(#857),#679,.F.);
#859=CARTESIAN_POINT('',(42.5,12.,-82.5));
#860=DIRECTION('',(-1.,0.,0.));
#861=DIRECTION('',(0.,0.,1.));
#862=AXIS2_PLACEMENT_3D('',#859,#860,#861);
#863=PLANE('',#862);
#864=DIRECTION('',(0.,-1.,0.));
#865=VECTOR('',#864,1.);
#866=CARTESIAN_POINT('',(42.5,12.,-72.5));
#867=LINE('',#866,#865);
#868=CARTESIAN_POINT('',(42.5,10.5,-72.5));
#869=VERTEX_POINT('',#868);
#870=EDGE_CURVE('E615',#522,#869,#867,.F.);
#871=ORIENTED_EDGE('',*,*,#870,.T.);
#872=DIRECTION('',(0.,0.,-1.));
#873=VECTOR('',#872,1.);
#874=CARTESIAN_POINT('',(42.5,10.5,-44.45));
#875=LINE('',#874,#873);
#876=CARTESIAN_POINT('',(42.5,10.5,-45.95));
#877=VERTEX_POINT('',#876);
#878=EDGE_CURVE('E752',#869,#877,#875,.F.);
#879=ORIENTED_EDGE('',*,*,#878,.T.);
#880=CARTESIAN_POINT('',(42.5,12.,-44.7343018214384));
#881=CARTESIAN_POINT('',(42.5,11.805839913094,-44.8336121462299));
#882=CARTESIAN_POINT('',(42.5,11.6242150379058,-44.9519430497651));
#883=CARTESIAN_POINT('',(42.5,11.280330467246,-45.2117989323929));
#884=CARTESIAN_POINT('',(42.5,11.1179206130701,-45.353120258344));
#885=CARTESIAN_POINT('',(42.5,10.8055770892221,-45.6445229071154));
#886=CARTESIAN_POINT('',(42.5,10.6555193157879,-45.7944818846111));
#887=CARTESIAN_POINT('',(42.5,10.5036514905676,-45.9463485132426));
#888=CARTESIAN_POINT('',(42.5,10.5018257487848,-45.9481742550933));
#889=CARTESIAN_POINT('',(42.5,10.5,-45.95));
#890=B_SPLINE_CURVE_WITH_KNOTS('',3,(#880,#881,#882,#883,#884,#885,#886,#887,#888,#889),
.UNSPECIFIED.,.F.,.F.,(4,2,2,2,4),(0.,0.649606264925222,1.29374362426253,1.93031747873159,
1.93806344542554),.UNSPECIFIED.);
#891=CARTESIAN_POINT('',(42.5,12.,-44.7343018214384));
#892=VERTEX_POINT('',#891);
#893=EDGE_CURVE('E900',#877,#892,#890,.F.);
#894=ORIENTED_EDGE('',*,*,#893,.T.);
#895=DIRECTION('',(0.,0.,-1.));
#896=VECTOR('',#895,1.);
#897=CARTESIAN_POINT('',(42.5,12.,-82.5));
#898=LINE('',#897,#896);
#899=CARTESIAN_POINT('',(42.5,12.,44.7343018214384));
#900=VERTEX_POINT('',#899);
#901=EDGE_CURVE('E65',#900,#892,#898,.T.);
#902=ORIENTED_EDGE('',*,*,#901,.F.);
#903=CARTESIAN_POINT('',(42.5,12.,44.7343018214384));
#904=CARTESIAN_POINT('',(42.5,11.8058399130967,44.8336121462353));
#905=CARTESIAN_POINT('',(42.5,11.6242150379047,44.9519430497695));
#906=CARTESIAN_POINT('',(42.5,11.2803304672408,45.2117989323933));
#907=CARTESIAN_POINT('',(42.5000000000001,11.1179206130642,45.353120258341));
#908=CARTESIAN_POINT('',(42.5,10.8055770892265,45.6445229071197));
#909=CARTESIAN_POINT('',(42.4999999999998,10.6555193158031,45.7944818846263));
#910=CARTESIAN_POINT('',(42.5,10.503651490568,45.946348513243));
#911=CARTESIAN_POINT('',(42.5,10.501825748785,45.9481742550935));
#912=CARTESIAN_POINT('',(42.5,10.5,45.95));
#913=B_SPLINE_CURVE_WITH_KNOTS('',3,(#903,#904,#905,#906,#907,#908,#909,#910,#911,#912),
.UNSPECIFIED.,.F.,.F.,(4,2,2,2,4),(0.,0.64960626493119,1.2937436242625,1.93031747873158,
1.93806344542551),.UNSPECIFIED.);
#914=CARTESIAN_POINT('',(42.5,10.5,45.95));
#915=VERTEX_POINT('',#914);
#916=EDGE_CURVE('E858',#900,#915,#913,.T.);
#917=ORIENTED_EDGE('',*,*,#916,.T.);
#918=DIRECTION('',(0.,0.,-1.));
#919=VECTOR('',#918,1.);
#920=CARTESIAN_POINT('',(42.5,10.5,72.5));
#921=LINE('',#920,#919);
#922=CARTESIAN_POINT('',(42.5,10.5,72.5));
#923=VERTEX_POINT('',#922);
#924=EDGE_CURVE('E750',#915,#923,#921,.F.);
#925=ORIENTED_EDGE('',*,*,#924,.T.);
#926=DIRECTION('',(0.,-1.,0.));
#927=VECTOR('',#926,1.);
#928=CARTESIAN_POINT('',(42.5,12.,72.5));
#929=LINE('',#928,#927);
#930=EDGE_CURVE('E613',#923,#530,#929,.T.);
#931=ORIENTED_EDGE('',*,*,#930,.T.);
#932=ORIENTED_EDGE('',*,*,#531,.T.);
#933=EDGE_LOOP('',(#871,#879,#894,#902,#917,#925,#931,#932));
#934=FACE_BOUND('',#933,.T.);
#935=ADVANCED_FACE('F910',(#934),#863,.F.);
#936=CARTESIAN_POINT('',(44.45,12.,44.45));
#937=DIRECTION('',(0.,1.,0.));
#938=DIRECTION('',(0.,0.,1.));
#939=AXIS2_PLACEMENT_3D('',#936,#937,#938);
#940=PLANE('',#939);
#941=DIRECTION('',(-1.,0.,0.));
#942=VECTOR('',#941,1.);
#943=CARTESIAN_POINT('',(44.45,12.,-44.45));
#944=LINE('',#943,#942);
#945=CARTESIAN_POINT('',(-43.5980762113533,12.,-44.45));
#946=VERTEX_POINT('',#945);
#947=EDGE_CURVE('E573',#946,#48,#944,.T.);
#948=ORIENTED_EDGE('',*,*,#947,.F.);
#949=CARTESIAN_POINT('',(-43.5980762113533,12.,-44.45));
#950=CARTESIAN_POINT('',(-43.5336500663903,12.,-44.4499908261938));
#951=CARTESIAN_POINT('',(-43.4692611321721,12.,-44.4531115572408));
#952=CARTESIAN_POINT('',(-43.341097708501,12.,-44.4651850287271));
#953=CARTESIAN_POINT('',(-43.2773226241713,12.,-44.4741313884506));
#954=CARTESIAN_POINT('',(-43.1518745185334,12.,-44.4972293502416));
#955=CARTESIAN_POINT('',(-43.0901842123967,12.,-44.5112885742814));
#956=CARTESIAN_POINT('',(-42.9680981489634,12.,-44.5441888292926));
#957=CARTESIAN_POINT('',(-42.9077024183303,12.,-44.563029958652));
#958=CARTESIAN_POINT('',(-42.7886955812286,12.,-44.6049562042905));
#959=CARTESIAN_POINT('',(-42.7300781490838,12.,-44.6280235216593));
#960=CARTESIAN_POINT('',(-42.6139928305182,12.,-44.6782283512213));
#961=CARTESIAN_POINT('',(-42.5565396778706,12.,-44.7054000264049));
#962=CARTESIAN_POINT('',(-42.5,12.,-44.7343018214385));
#963=B_SPLINE_CURVE_WITH_KNOTS('',3,(#949,#950,#951,#952,#953,#954,#955,#956,#957,#958,#959,
#960,#961,#962),.UNSPECIFIED.,.F.,.F.,(4,2,2,2,2,2,4),(0.,0.193148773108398,0.386086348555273,
0.575698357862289,0.765314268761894,0.954149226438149,1.14465271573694),.UNSPECIFIED.);
#964=EDGE_CURVE('E50',#946,#741,#963,.T.);
#965=ORIENTED_EDGE('',*,*,#964,.T.);
#966=ORIENTED_EDGE('',*,*,#744,.T.);
#967=CARTESIAN_POINT('',(-42.5,12.,44.7343018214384));
#968=CARTESIAN_POINT('',(-42.5568888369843,12.,44.7052311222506));
#969=CARTESIAN_POINT('',(-42.6146601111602,12.,44.6779170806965));
#970=CARTESIAN_POINT('',(-42.7320009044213,12.,44.6272150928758));
#971=CARTESIAN_POINT('',(-42.7915730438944,12.,44.6038332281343));
#972=CARTESIAN_POINT('',(-42.9703119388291,12.,44.5411968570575));
#973=CARTESIAN_POINT('',(-43.0918302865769,12.,44.5082308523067));
#974=CARTESIAN_POINT('',(-43.277991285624,12.,44.4740362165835));
#975=CARTESIAN_POINT('',(-43.3412950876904,12.,44.4651717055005));
#976=CARTESIAN_POINT('',(-43.4690657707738,12.,44.45312465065));
#977=CARTESIAN_POINT('',(-43.5335379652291,12.,44.4499990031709));
#978=CARTESIAN_POINT('',(-43.5980762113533,12.,44.45));
#979=B_SPLINE_CURVE_WITH_KNOTS('',3,(#967,#968,#969,#970,#971,#972,#973,#974,#975,#976,#977,
#978),.UNSPECIFIED.,.F.,.F.,(4,2,2,2,2,4),(0.,0.191586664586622,0.38346696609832,
0.759403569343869,0.950941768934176,1.14436887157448),.UNSPECIFIED.);
#980=CARTESIAN_POINT('',(-43.5980762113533,12.,44.45));
#981=VERTEX_POINT('',#980);
#982=EDGE_CURVE('E895',#743,#981,#979,.T.);
#983=ORIENTED_EDGE('',*,*,#982,.T.);
#984=DIRECTION('',(-1.,0.,0.));
#985=VECTOR('',#984,1.);
#986=CARTESIAN_POINT('',(44.45,12.,44.45));
#987=LINE('',#986,#985);
#988=EDGE_CURVE('E577',#981,#56,#987,.T.);
#989=ORIENTED_EDGE('',*,*,#988,.T.);
#990=ORIENTED_EDGE('',*,*,#57,.T.);
#991=EDGE_LOOP('',(#948,#965,#966,#983,#989,#990));
#992=FACE_BOUND('',#991,.T.);
#993=ADVANCED_FACE('F864',(#992),#940,.F.);
#994=CARTESIAN_POINT('',(43.5980762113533,12.,44.45));
#995=VERTEX_POINT('',#994);
#996=EDGE_CURVE('E578',#201,#995,#987,.T.);
#997=ORIENTED_EDGE('',*,*,#996,.T.);
#998=CARTESIAN_POINT('',(43.5980762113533,12.,44.45));
#999=CARTESIAN_POINT('',(43.5336500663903,12.,44.4499908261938));
#1000=CARTESIAN_POINT('',(43.469261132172,12.,44.4531115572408));
#1001=CARTESIAN_POINT('',(43.341097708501,12.,44.4651850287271));
#1002=CARTESIAN_POINT('',(43.2773226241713,12.,44.4741313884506));
#1003=CARTESIAN_POINT('',(43.1518745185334,12.,44.4972293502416));
#1004=CARTESIAN_POINT('',(43.0901842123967,12.,44.5112885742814));
#1005=CARTESIAN_POINT('',(42.9680981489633,12.,44.5441888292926));
#1006=CARTESIAN_POINT('',(42.9077024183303,12.,44.563029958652));
#1007=CARTESIAN_POINT('',(42.7886955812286,12.,44.6049562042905));
#1008=CARTESIAN_POINT('',(42.7300781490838,12.,44.6280235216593));
#1009=CARTESIAN_POINT('',(42.6139928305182,12.,44.6782283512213));
#1010=CARTESIAN_POINT('',(42.5565396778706,12.,44.7054000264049));
#1011=CARTESIAN_POINT('',(42.5,12.,44.7343018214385));
#1012=B_SPLINE_CURVE_WITH_KNOTS('',3,(#998,#999,#1000,#1001,#1002,#1003,#1004,#1005,#1006,#1007,
#1008,#1009,#1010,#1011),.UNSPECIFIED.,.F.,.F.,(4,2,2,2,2,2,4),(0.,0.193148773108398,
0.386086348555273,0.575698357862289,0.765314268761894,0.954149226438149,1.14465271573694),.UNSPECIFIED.);
#1013=EDGE_CURVE('E851',#995,#900,#1012,.T.);
#1014=ORIENTED_EDGE('',*,*,#1013,.T.);
#1015=ORIENTED_EDGE('',*,*,#901,.T.);
#1016=CARTESIAN_POINT('',(42.5,12.,-44.7343018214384));
#1017=CARTESIAN_POINT('',(42.5568888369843,12.,-44.7052311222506));
#1018=CARTESIAN_POINT('',(42.6146601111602,12.,-44.6779170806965));
#1019=CARTESIAN_POINT('',(42.7320009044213,12.,-44.6272150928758));
#1020=CARTESIAN_POINT('',(42.7915730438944,12.,-44.6038332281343));
#1021=CARTESIAN_POINT('',(42.9703119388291,12.,-44.5411968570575));
#1022=CARTESIAN_POINT('',(43.0918302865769,12.,-44.5082308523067));
#1023=CARTESIAN_POINT('',(43.277991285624,12.,-44.4740362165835));
#1024=CARTESIAN_POINT('',(43.3412950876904,12.,-44.4651717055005));
#1025=CARTESIAN_POINT('',(43.4690657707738,12.,-44.45312465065));
#1026=CARTESIAN_POINT('',(43.5335379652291,12.,-44.4499990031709));
#1027=CARTESIAN_POINT('',(43.5980762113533,12.,-44.45));
#1028=B_SPLINE_CURVE_WITH_KNOTS('',3,(#1016,#1017,#1018,#1019,#1020,#1021,#1022,#1023,#1024,
#1025,#1026,#1027),.UNSPECIFIED.,.F.,.F.,(4,2,2,2,2,4),(0.,0.191586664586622,0.38346696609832,
0.759403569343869,0.950941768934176,1.14436887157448),.UNSPECIFIED.);
#1029=CARTESIAN_POINT('',(43.5980762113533,12.,-44.45));
#1030=VERTEX_POINT('',#1029);
#1031=EDGE_CURVE('E905',#892,#1030,#1028,.T.);
#1032=ORIENTED_EDGE('',*,*,#1031,.T.);
#1033=EDGE_CURVE('E574',#148,#1030,#944,.T.);
#1034=ORIENTED_EDGE('',*,*,#1033,.F.);
#1035=ORIENTED_EDGE('',*,*,#208,.F.);
#1036=EDGE_LOOP('',(#997,#1014,#1015,#1032,#1034,#1035));
#1037=FACE_BOUND('',#1036,.T.);
#1038=ADVANCED_FACE('F1577',(#1037),#940,.F.);
#1039=CARTESIAN_POINT('',(44.45,12.,44.45));
#1040=DIRECTION('',(0.,0.,-1.));
#1041=DIRECTION('',(-1.,0.,0.));
#1042=AXIS2_PLACEMENT_3D('',#1039,#1040,#1041);
#1043=PLANE('',#1042);
#1044=DIRECTION('',(-1.,0.,0.));
#1045=VECTOR('',#1044,1.);
#1046=CARTESIAN_POINT('',(44.45,13.5,44.45));
#1047=LINE('',#1046,#1045);
#1048=CARTESIAN_POINT('',(-41.,13.5,44.45));
#1049=VERTEX_POINT('',#1048);
#1050=CARTESIAN_POINT('',(41.,13.5,44.45));
#1051=VERTEX_POINT('',#1050);
#1052=EDGE_CURVE('E755',#1049,#1051,#1047,.F.);
#1053=ORIENTED_EDGE('',*,*,#1052,.T.);
#1054=CARTESIAN_POINT('',(41.,10.5,44.45));
#1055=DIRECTION('',(0.,0.,-1.));
#1056=DIRECTION('',(-1.,0.,0.));
#1057=AXIS2_PLACEMENT_3D('',#1054,#1055,#1056);
#1058=CIRCLE('',#1057,3.);
#1059=EDGE_CURVE('E829',#1051,#995,#1058,.T.);
#1060=ORIENTED_EDGE('',*,*,#1059,.T.);
#1061=ORIENTED_EDGE('',*,*,#996,.F.);
#1062=ORIENTED_EDGE('',*,*,#202,.F.);
#1063=DIRECTION('',(-1.,0.,0.));
#1064=VECTOR('',#1063,1.);
#1065=CARTESIAN_POINT('',(44.45,25.3490095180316,44.45));
#1066=LINE('',#1065,#1064);
#1067=EDGE_CURVE('E745',#193,#64,#1066,.T.);
#1068=ORIENTED_EDGE('',*,*,#1067,.T.);
#1069=ORIENTED_EDGE('',*,*,#65,.T.);
#1070=ORIENTED_EDGE('',*,*,#988,.F.);
#1071=CARTESIAN_POINT('',(-41.,10.5,44.45));
#1072=DIRECTION('',(0.,0.,-1.));
#1073=DIRECTION('',(-1.,0.,0.));
#1074=AXIS2_PLACEMENT_3D('',#1071,#1072,#1073);
#1075=CIRCLE('',#1074,3.);
#1076=EDGE_CURVE('E827',#981,#1049,#1075,.T.);
#1077=ORIENTED_EDGE('',*,*,#1076,.T.);
#1078=EDGE_LOOP('',(#1053,#1060,#1061,#1062,#1068,#1069,#1070,#1077));
#1079=FACE_BOUND('',#1078,.T.);
#1080=ADVANCED_FACE('F993',(#1079),#1043,.F.);
#1081=CARTESIAN_POINT('',(44.45,12.,-44.45));
#1082=DIRECTION('',(0.,0.,1.));
#1083=DIRECTION('',(1.,0.,0.));
#1084=AXIS2_PLACEMENT_3D('',#1081,#1082,#1083);
#1085=PLANE('',#1084);
#1086=ORIENTED_EDGE('',*,*,#1033,.T.);
#1087=CARTESIAN_POINT('',(41.,10.5,-44.45));
#1088=DIRECTION('',(0.,0.,1.));
#1089=DIRECTION('',(1.,0.,0.));
#1090=AXIS2_PLACEMENT_3D('',#1087,#1088,#1089);
#1091=CIRCLE('',#1090,3.);
#1092=CARTESIAN_POINT('',(41.,13.5,-44.45));
#1093=VERTEX_POINT('',#1092);
#1094=EDGE_CURVE('E840',#1030,#1093,#1091,.T.);
#1095=ORIENTED_EDGE('',*,*,#1094,.T.);
#1096=DIRECTION('',(-1.,0.,0.));
#1097=VECTOR('',#1096,1.);
#1098=CARTESIAN_POINT('',(44.45,13.5,-44.45));
#1099=LINE('',#1098,#1097);
#1100=CARTESIAN_POINT('',(-41.,13.5,-44.45));
#1101=VERTEX_POINT('',#1100);
#1102=EDGE_CURVE('E836',#1093,#1101,#1099,.T.);
#1103=ORIENTED_EDGE('',*,*,#1102,.T.);
#1104=CARTESIAN_POINT('',(-41.,10.5,-44.45));
#1105=DIRECTION('',(0.,0.,1.));
#1106=DIRECTION('',(1.,0.,0.));
#1107=AXIS2_PLACEMENT_3D('',#1104,#1105,#1106);
#1108=CIRCLE('',#1107,3.);
#1109=EDGE_CURVE('E838',#1101,#946,#1108,.T.);
#1110=ORIENTED_EDGE('',*,*,#1109,.T.);
#1111=ORIENTED_EDGE('',*,*,#947,.T.);
#1112=ORIENTED_EDGE('',*,*,#49,.T.);
#1113=DIRECTION('',(-1.,0.,0.));
#1114=VECTOR('',#1113,1.);
#1115=CARTESIAN_POINT('',(44.45,25.3490095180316,-44.45));
#1116=LINE('',#1115,#1114);
#1117=EDGE_CURVE('E739',#40,#150,#1116,.F.);
#1118=ORIENTED_EDGE('',*,*,#1117,.T.);
#1119=ORIENTED_EDGE('',*,*,#151,.F.);
#1120=EDGE_LOOP('',(#1086,#1095,#1103,#1110,#1111,#1112,#1118,#1119));
#1121=FACE_BOUND('',#1120,.T.);
#1122=ADVANCED_FACE('F958',(#1121),#1085,.F.);
#1123=CARTESIAN_POINT('',(44.45,26.5,-44.45));
#1124=DIRECTION('',(0.,-0.965925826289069,0.258819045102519));
#1125=DIRECTION('',(0.,-0.258819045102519,-0.965925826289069));
#1126=AXIS2_PLACEMENT_3D('',#1123,#1124,#1125);
#1127=PLANE('',#1126);
#1128=ORIENTED_EDGE('',*,*,#168,.F.);
#1129=DIRECTION('',(-1.,0.,0.));
#1130=VECTOR('',#1129,1.);
#1131=CARTESIAN_POINT('',(44.45,26.7978982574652,-43.3382285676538));
#1132=LINE('',#1131,#1130);
#1133=EDGE_CURVE('E732',#159,#29,#1132,.T.);
#1134=ORIENTED_EDGE('',*,*,#1133,.T.);
#1135=ORIENTED_EDGE('',*,*,#32,.T.);
#1136=DIRECTION('',(-1.,0.,0.));
#1137=VECTOR('',#1136,1.);
#1138=CARTESIAN_POINT('',(44.45,28.8754645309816,-35.584645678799));
#1139=LINE('',#1138,#1137);
#1140=EDGE_CURVE('E570',#167,#31,#1139,.T.);
#1141=ORIENTED_EDGE('',*,*,#1140,.F.);
#1142=EDGE_LOOP('',(#1128,#1134,#1135,#1141));
#1143=FACE_BOUND('',#1142,.T.);
#1144=ADVANCED_FACE('F979',(#1143),#1127,.F.);
#1145=CARTESIAN_POINT('',(44.45,64.,0.));
#1146=DIRECTION('',(-1.,0.,0.));
#1147=DIRECTION('',(0.,0.,1.));
#1148=AXIS2_PLACEMENT_3D('',#1145,#1146,#1147);
#1149=CYLINDRICAL_SURFACE('',#1148,50.);
#1150=ORIENTED_EDGE('',*,*,#89,.T.);
#1151=DIRECTION('',(-1.,0.,0.));
#1152=VECTOR('',#1151,1.);
#1153=CARTESIAN_POINT('',(44.45,28.8754645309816,35.584645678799));
#1154=LINE('',#1153,#1152);
#1155=EDGE_CURVE('E553',#176,#81,#1154,.T.);
#1156=ORIENTED_EDGE('',*,*,#1155,.F.);
#1157=ORIENTED_EDGE('',*,*,#177,.F.);
#1158=ORIENTED_EDGE('',*,*,#1140,.T.);
#1159=EDGE_LOOP('',(#1150,#1156,#1157,#1158));
#1160=FACE_BOUND('',#1159,.T.);
#1161=ADVANCED_FACE('F984',(#1160),#1149,.F.);
#1162=CARTESIAN_POINT('',(44.45,26.5,44.45));
#1163=DIRECTION('',(0.,-0.965925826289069,-0.258819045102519));
#1164=DIRECTION('',(0.,0.258819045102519,-0.965925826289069));
#1165=AXIS2_PLACEMENT_3D('',#1162,#1163,#1164);
#1166=PLANE('',#1165);
#1167=ORIENTED_EDGE('',*,*,#82,.T.);
#1168=DIRECTION('',(-1.,0.,0.));
#1169=VECTOR('',#1168,1.);
#1170=CARTESIAN_POINT('',(44.45,26.7978982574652,43.3382285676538));
#1171=LINE('',#1170,#1169);
#1172=EDGE_CURVE('E748',#73,#184,#1171,.F.);
#1173=ORIENTED_EDGE('',*,*,#1172,.T.);
#1174=ORIENTED_EDGE('',*,*,#185,.F.);
#1175=ORIENTED_EDGE('',*,*,#1155,.T.);
#1176=EDGE_LOOP('',(#1167,#1173,#1174,#1175));
#1177=FACE_BOUND('',#1176,.T.);
#1178=ADVANCED_FACE('F996',(#1177),#1166,.F.);
#1179=CARTESIAN_POINT('',(-7.24999999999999,-0.000999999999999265,82.5));
#1180=DIRECTION('',(-1.,0.,0.));
#1181=DIRECTION('',(0.,0.,1.));
#1182=AXIS2_PLACEMENT_3D('',#1179,#1180,#1181);
#1183=PLANE('',#1182);
#1184=ORIENTED_EDGE('',*,*,#573,.T.);
#1185=DIRECTION('',(0.,1.,0.));
#1186=VECTOR('',#1185,1.);
#1187=CARTESIAN_POINT('',(-7.25,-0.000999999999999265,71.5));
#1188=LINE('',#1187,#1186);
#1189=CARTESIAN_POINT('',(-7.25,14.,71.5));
#1190=VERTEX_POINT('',#1189);
#1191=EDGE_CURVE('E529',#564,#1190,#1188,.T.);
#1192=ORIENTED_EDGE('',*,*,#1191,.T.);
#1193=DIRECTION('',(0.,0.,-1.));
#1194=VECTOR('',#1193,1.);
#1195=CARTESIAN_POINT('',(-7.25,14.,71.5));
#1196=LINE('',#1195,#1194);
#1197=EDGE_CURVE('E512',#687,#1190,#1196,.T.);
#1198=ORIENTED_EDGE('',*,*,#1197,.F.);
#1199=ORIENTED_EDGE('',*,*,#726,.F.);
#1200=EDGE_LOOP('',(#1184,#1192,#1198,#1199));
#1201=FACE_BOUND('',#1200,.T.);
#1202=ADVANCED_FACE('F998',(#1201),#1183,.F.);
#1203=CARTESIAN_POINT('',(0.,-0.000999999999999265,71.5));
#1204=DIRECTION('',(0.,1.,0.));
#1205=DIRECTION('',(0.,0.,1.));
#1206=AXIS2_PLACEMENT_3D('',#1203,#1204,#1205);
#1207=CYLINDRICAL_SURFACE('',#1206,7.25);
#1208=ORIENTED_EDGE('',*,*,#565,.T.);
#1209=DIRECTION('',(0.,1.,0.));
#1210=VECTOR('',#1209,1.);
#1211=CARTESIAN_POINT('',(7.25000000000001,-0.000999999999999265,71.5));
#1212=LINE('',#1211,#1210);
#1213=CARTESIAN_POINT('',(7.25000000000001,14.,71.5));
#1214=VERTEX_POINT('',#1213);
#1215=EDGE_CURVE('E532',#555,#1214,#1212,.T.);
#1216=ORIENTED_EDGE('',*,*,#1215,.T.);
#1217=CARTESIAN_POINT('',(0.,14.,71.5));
#1218=DIRECTION('',(0.,-1.,0.));
#1219=DIRECTION('',(0.,0.,1.));
#1220=AXIS2_PLACEMENT_3D('',#1217,#1218,#1219);
#1221=CIRCLE('',#1220,7.25);
#1222=EDGE_CURVE('E494',#1190,#1214,#1221,.T.);
#1223=ORIENTED_EDGE('',*,*,#1222,.F.);
#1224=ORIENTED_EDGE('',*,*,#1191,.F.);
#1225=EDGE_LOOP('',(#1208,#1216,#1223,#1224));
#1226=FACE_BOUND('',#1225,.T.);
#1227=ADVANCED_FACE('F1004',(#1226),#1207,.F.);
#1228=CARTESIAN_POINT('',(7.25000000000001,-0.000999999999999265,82.5));
#1229=DIRECTION('',(1.,0.,0.));
#1230=DIRECTION('',(0.,0.,-1.));
#1231=AXIS2_PLACEMENT_3D('',#1228,#1229,#1230);
#1232=PLANE('',#1231);
#1233=ORIENTED_EDGE('',*,*,#556,.T.);
#1234=ORIENTED_EDGE('',*,*,#839,.T.);
#1235=DIRECTION('',(0.,0.,1.));
#1236=VECTOR('',#1235,1.);
#1237=CARTESIAN_POINT('',(7.25000000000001,14.,82.5));
#1238=LINE('',#1237,#1236);
#1239=EDGE_CURVE('E497',#1214,#832,#1238,.T.);
#1240=ORIENTED_EDGE('',*,*,#1239,.F.);
#1241=ORIENTED_EDGE('',*,*,#1215,.F.);
#1242=EDGE_LOOP('',(#1233,#1234,#1240,#1241));
#1243=FACE_BOUND('',#1242,.T.);
#1244=ADVANCED_FACE('F1015',(#1243),#1232,.F.);
#1245=CARTESIAN_POINT('',(12.75,14.,82.5));
#1246=DIRECTION('',(-1.,0.,0.));
#1247=DIRECTION('',(0.,0.,1.));
#1248=AXIS2_PLACEMENT_3D('',#1245,#1246,#1247);
#1249=PLANE('',#1248);
#1250=DIRECTION('',(0.,0.,-1.));
#1251=VECTOR('',#1250,1.);
#1252=CARTESIAN_POINT('',(12.75,14.,82.5));
#1253=LINE('',#1252,#1251);
#1254=CARTESIAN_POINT('',(12.75,14.,81.));
#1255=VERTEX_POINT('',#1254);
#1256=CARTESIAN_POINT('',(12.75,14.,71.5));
#1257=VERTEX_POINT('',#1256);
#1258=EDGE_CURVE('E503',#1255,#1257,#1253,.T.);
#1259=ORIENTED_EDGE('',*,*,#1258,.F.);
#1260=DIRECTION('',(0.,-1.,0.));
#1261=VECTOR('',#1260,1.);
#1262=CARTESIAN_POINT('',(12.75,14.,81.));
#1263=LINE('',#1262,#1261);
#1264=CARTESIAN_POINT('',(12.75,13.5,81.));
#1265=VERTEX_POINT('',#1264);
#1266=EDGE_CURVE('E668',#1255,#1265,#1263,.T.);
#1267=ORIENTED_EDGE('',*,*,#1266,.T.);
#1268=DIRECTION('',(0.,0.,-1.));
#1269=VECTOR('',#1268,1.);
#1270=CARTESIAN_POINT('',(12.75,13.5,82.5));
#1271=LINE('',#1270,#1269);
#1272=CARTESIAN_POINT('',(12.75,13.5,71.5));
#1273=VERTEX_POINT('',#1272);
#1274=EDGE_CURVE('E666',#1265,#1273,#1271,.T.);
#1275=ORIENTED_EDGE('',*,*,#1274,.T.);
#1276=DIRECTION('',(0.,-1.,0.));
#1277=VECTOR('',#1276,1.);
#1278=CARTESIAN_POINT('',(12.75,14.,71.5));
#1279=LINE('',#1278,#1277);
#1280=EDGE_CURVE('E518',#1257,#1273,#1279,.T.);
#1281=ORIENTED_EDGE('',*,*,#1280,.F.);
#1282=EDGE_LOOP('',(#1259,#1267,#1275,#1281));
#1283=FACE_BOUND('',#1282,.T.);
#1284=ADVANCED_FACE('F1018',(#1283),#1249,.F.);
#1285=CARTESIAN_POINT('',(0.,14.,71.5));
#1286=DIRECTION('',(0.,-1.,0.));
#1287=DIRECTION('',(0.,0.,-1.));
#1288=AXIS2_PLACEMENT_3D('',#1285,#1286,#1287);
#1289=CYLINDRICAL_SURFACE('',#1288,12.75);
#1290=ORIENTED_EDGE('',*,*,#1280,.T.);
#1291=CARTESIAN_POINT('',(0.,13.5,71.5));
#1292=DIRECTION('',(0.,1.,0.));
#1293=DIRECTION('',(0.,0.,1.));
#1294=AXIS2_PLACEMENT_3D('',#1291,#1292,#1293);
#1295=CIRCLE('',#1294,12.75);
#1296=CARTESIAN_POINT('',(-12.75,13.5,71.5));
#1297=VERTEX_POINT('',#1296);
#1298=EDGE_CURVE('E728',#1273,#1297,#1295,.T.);
#1299=ORIENTED_EDGE('',*,*,#1298,.T.);
#1300=DIRECTION('',(0.,-1.,0.));
#1301=VECTOR('',#1300,1.);
#1302=CARTESIAN_POINT('',(-12.75,14.,71.5));
#1303=LINE('',#1302,#1301);
#1304=CARTESIAN_POINT('',(-12.75,14.,71.5));
#1305=VERTEX_POINT('',#1304);
#1306=EDGE_CURVE('E515',#1305,#1297,#1303,.T.);
#1307=ORIENTED_EDGE('',*,*,#1306,.F.);
#1308=CARTESIAN_POINT('',(0.,14.,71.5));
#1309=DIRECTION('',(0.,1.,0.));
#1310=DIRECTION('',(0.,0.,1.));
#1311=AXIS2_PLACEMENT_3D('',#1308,#1309,#1310);
#1312=CIRCLE('',#1311,12.75);
#1313=EDGE_CURVE('E505',#1257,#1305,#1312,.T.);
#1314=ORIENTED_EDGE('',*,*,#1313,.F.);
#1315=EDGE_LOOP('',(#1290,#1299,#1307,#1314));
#1316=FACE_BOUND('',#1315,.T.);
#1317=ADVANCED_FACE('F1025',(#1316),#1289,.T.);
#1318=CARTESIAN_POINT('',(-12.75,14.,71.5));
#1319=DIRECTION('',(1.,0.,0.));
#1320=DIRECTION('',(0.,0.,-1.));
#1321=AXIS2_PLACEMENT_3D('',#1318,#1319,#1320);
#1322=PLANE('',#1321);
#1323=DIRECTION('',(0.,0.,1.));
#1324=VECTOR('',#1323,1.);
#1325=CARTESIAN_POINT('',(-12.75,13.5,71.5));
#1326=LINE('',#1325,#1324);
#1327=CARTESIAN_POINT('',(-12.75,13.5,81.));
#1328=VERTEX_POINT('',#1327);
#1329=EDGE_CURVE('E658',#1297,#1328,#1326,.T.);
#1330=ORIENTED_EDGE('',*,*,#1329,.T.);
#1331=DIRECTION('',(0.,-1.,0.));
#1332=VECTOR('',#1331,1.);
#1333=CARTESIAN_POINT('',(-12.75,14.,81.));
#1334=LINE('',#1333,#1332);
#1335=CARTESIAN_POINT('',(-12.75,14.,81.));
#1336=VERTEX_POINT('',#1335);
#1337=EDGE_CURVE('E660',#1328,#1336,#1334,.F.);
#1338=ORIENTED_EDGE('',*,*,#1337,.T.);
#1339=DIRECTION('',(0.,0.,1.));
#1340=VECTOR('',#1339,1.);
#1341=CARTESIAN_POINT('',(-12.75,14.,71.5));
#1342=LINE('',#1341,#1340);
#1343=EDGE_CURVE('E507',#1305,#1336,#1342,.T.);
#1344=ORIENTED_EDGE('',*,*,#1343,.F.);
#1345=ORIENTED_EDGE('',*,*,#1306,.T.);
#1346=EDGE_LOOP('',(#1330,#1338,#1344,#1345));
#1347=FACE_BOUND('',#1346,.T.);
#1348=ADVANCED_FACE('F1029',(#1347),#1322,.F.);
#1349=CARTESIAN_POINT('',(0.,14.,71.5));
#1350=DIRECTION('',(0.,1.,0.));
#1351=DIRECTION('',(0.,0.,1.));
#1352=AXIS2_PLACEMENT_3D('',#1349,#1350,#1351);
#1353=PLANE('',#1352);
#1354=ORIENTED_EDGE('',*,*,#1343,.T.);
#1355=CARTESIAN_POINT('',(-11.25,14.,81.));
#1356=DIRECTION('',(0.,1.,0.));
#1357=DIRECTION('',(0.,0.,1.));
#1358=AXIS2_PLACEMENT_3D('',#1355,#1356,#1357);
#1359=CIRCLE('',#1358,1.5);
#1360=EDGE_CURVE('E664',#1336,#685,#1359,.T.);
#1361=ORIENTED_EDGE('',*,*,#1360,.T.);
#1362=ORIENTED_EDGE('',*,*,#688,.T.);
#1363=ORIENTED_EDGE('',*,*,#1197,.T.);
#1364=ORIENTED_EDGE('',*,*,#1222,.T.);
#1365=ORIENTED_EDGE('',*,*,#1239,.T.);
#1366=ORIENTED_EDGE('',*,*,#833,.T.);
#1367=CARTESIAN_POINT('',(11.25,14.,81.));
#1368=DIRECTION('',(0.,1.,0.));
#1369=DIRECTION('',(0.,0.,1.));
#1370=AXIS2_PLACEMENT_3D('',#1367,#1368,#1369);
#1371=CIRCLE('',#1370,1.5);
#1372=EDGE_CURVE('E662',#824,#1255,#1371,.T.);
#1373=ORIENTED_EDGE('',*,*,#1372,.T.);
#1374=ORIENTED_EDGE('',*,*,#1258,.T.);
#1375=ORIENTED_EDGE('',*,*,#1313,.T.);
#1376=EDGE_LOOP('',(#1354,#1361,#1362,#1363,#1364,#1365,#1366,#1373,#1374,#1375));
#1377=FACE_BOUND('',#1376,.T.);
#1378=ADVANCED_FACE('F1033',(#1377),#1353,.T.);
#1379=CARTESIAN_POINT('',(-7.24999999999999,-0.000999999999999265,-82.5));
#1380=DIRECTION('',(1.,0.,0.));
#1381=DIRECTION('',(0.,0.,-1.));
#1382=AXIS2_PLACEMENT_3D('',#1379,#1380,#1381);
#1383=PLANE('',#1382);
#1384=ORIENTED_EDGE('',*,*,#295,.T.);
#1385=DIRECTION('',(0.,0.,1.));
#1386=VECTOR('',#1385,1.);
#1387=CARTESIAN_POINT('',(-7.25,14.,-71.5));
#1388=LINE('',#1387,#1386);
#1389=CARTESIAN_POINT('',(-7.25,14.,-71.5));
#1390=VERTEX_POINT('',#1389);
#1391=EDGE_CURVE('E451',#286,#1390,#1388,.T.);
#1392=ORIENTED_EDGE('',*,*,#1391,.T.);
#1393=DIRECTION('',(0.,1.,0.));
#1394=VECTOR('',#1393,1.);
#1395=CARTESIAN_POINT('',(-7.25,-0.000999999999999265,-71.5));
#1396=LINE('',#1395,#1394);
#1397=EDGE_CURVE('E482',#497,#1390,#1396,.T.);
#1398=ORIENTED_EDGE('',*,*,#1397,.F.);
#1399=ORIENTED_EDGE('',*,*,#498,.F.);
#1400=EDGE_LOOP('',(#1384,#1392,#1398,#1399));
#1401=FACE_BOUND('',#1400,.T.);
#1402=ADVANCED_FACE('F1037',(#1401),#1383,.T.);
#1403=CARTESIAN_POINT('',(7.25000000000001,-0.000999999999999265,-82.5));
#1404=DIRECTION('',(-1.,0.,0.));
#1405=DIRECTION('',(0.,0.,1.));
#1406=AXIS2_PLACEMENT_3D('',#1403,#1404,#1405);
#1407=PLANE('',#1406);
#1408=DIRECTION('',(0.,1.,0.));
#1409=VECTOR('',#1408,1.);
#1410=CARTESIAN_POINT('',(7.25000000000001,-0.000999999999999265,-71.5));
#1411=LINE('',#1410,#1409);
#1412=CARTESIAN_POINT('',(7.25000000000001,14.,-71.5));
#1413=VERTEX_POINT('',#1412);
#1414=EDGE_CURVE('E489',#506,#1413,#1411,.T.);
#1415=ORIENTED_EDGE('',*,*,#1414,.T.);
#1416=DIRECTION('',(0.,0.,-1.));
#1417=VECTOR('',#1416,1.);
#1418=CARTESIAN_POINT('',(7.25000000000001,14.,-82.5));
#1419=LINE('',#1418,#1417);
#1420=EDGE_CURVE('E467',#1413,#327,#1419,.T.);
#1421=ORIENTED_EDGE('',*,*,#1420,.T.);
#1422=ORIENTED_EDGE('',*,*,#373,.F.);
#1423=ORIENTED_EDGE('',*,*,#513,.F.);
#1424=EDGE_LOOP('',(#1415,#1421,#1422,#1423));
#1425=FACE_BOUND('',#1424,.T.);
#1426=ADVANCED_FACE('F1041',(#1425),#1407,.T.);
#1427=CARTESIAN_POINT('',(0.,-0.000999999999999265,-71.5));
#1428=DIRECTION('',(0.,1.,0.));
#1429=DIRECTION('',(0.,0.,1.));
#1430=AXIS2_PLACEMENT_3D('',#1427,#1428,#1429);
#1431=CYLINDRICAL_SURFACE('',#1430,7.25);
#1432=ORIENTED_EDGE('',*,*,#1397,.T.);
#1433=CARTESIAN_POINT('',(0.,14.,-71.5));
#1434=DIRECTION('',(0.,1.,0.));
#1435=DIRECTION('',(0.,0.,-1.));
#1436=AXIS2_PLACEMENT_3D('',#1433,#1434,#1435);
#1437=CIRCLE('',#1436,7.25);
#1438=EDGE_CURVE('E448',#1390,#1413,#1437,.T.);
#1439=ORIENTED_EDGE('',*,*,#1438,.T.);
#1440=ORIENTED_EDGE('',*,*,#1414,.F.);
#1441=ORIENTED_EDGE('',*,*,#507,.F.);
#1442=EDGE_LOOP('',(#1432,#1439,#1440,#1441));
#1443=FACE_BOUND('',#1442,.T.);
#1444=ADVANCED_FACE('F1043',(#1443),#1431,.F.);
#1445=CARTESIAN_POINT('',(-12.75,14.,-71.5));
#1446=DIRECTION('',(-1.,0.,0.));
#1447=DIRECTION('',(0.,0.,1.));
#1448=AXIS2_PLACEMENT_3D('',#1445,#1446,#1447);
#1449=PLANE('',#1448);
#1450=DIRECTION('',(0.,0.,-1.));
#1451=VECTOR('',#1450,1.);
#1452=CARTESIAN_POINT('',(-12.75,14.,-71.5));
#1453=LINE('',#1452,#1451);
#1454=CARTESIAN_POINT('',(-12.75,14.,-71.5));
#1455=VERTEX_POINT('',#1454);
#1456=CARTESIAN_POINT('',(-12.75,14.,-81.));
#1457=VERTEX_POINT('',#1456);
#1458=EDGE_CURVE('E456',#1455,#1457,#1453,.T.);
#1459=ORIENTED_EDGE('',*,*,#1458,.T.);
#1460=DIRECTION('',(0.,-1.,0.));
#1461=VECTOR('',#1460,1.);
#1462=CARTESIAN_POINT('',(-12.75,12.,-81.));
#1463=LINE('',#1462,#1461);
#1464=CARTESIAN_POINT('',(-12.75,13.5,-81.));
#1465=VERTEX_POINT('',#1464);
#1466=EDGE_CURVE('E625',#1457,#1465,#1463,.T.);
#1467=ORIENTED_EDGE('',*,*,#1466,.T.);
#1468=DIRECTION('',(0.,0.,-1.));
#1469=VECTOR('',#1468,1.);
#1470=CARTESIAN_POINT('',(-12.75,13.5,-71.5));
#1471=LINE('',#1470,#1469);
#1472=CARTESIAN_POINT('',(-12.75,13.5,-71.5));
#1473=VERTEX_POINT('',#1472);
#1474=EDGE_CURVE('E623',#1465,#1473,#1471,.F.);
#1475=ORIENTED_EDGE('',*,*,#1474,.T.);
#1476=DIRECTION('',(0.,-1.,0.));
#1477=VECTOR('',#1476,1.);
#1478=CARTESIAN_POINT('',(-12.75,14.,-71.5));
#1479=LINE('',#1478,#1477);
#1480=EDGE_CURVE('E473',#1455,#1473,#1479,.T.);
#1481=ORIENTED_EDGE('',*,*,#1480,.F.);
#1482=EDGE_LOOP('',(#1459,#1467,#1475,#1481));
#1483=FACE_BOUND('',#1482,.T.);
#1484=ADVANCED_FACE('F1046',(#1483),#1449,.T.);
#1485=CARTESIAN_POINT('',(0.,14.,-71.5));
#1486=DIRECTION('',(0.,-1.,0.));
#1487=DIRECTION('',(0.,0.,-1.));
#1488=AXIS2_PLACEMENT_3D('',#1485,#1486,#1487);
#1489=CYLINDRICAL_SURFACE('',#1488,12.75);
#1490=ORIENTED_EDGE('',*,*,#1480,.T.);
#1491=CARTESIAN_POINT('',(0.,13.5,-71.5));
#1492=DIRECTION('',(0.,1.,0.));
#1493=DIRECTION('',(0.,0.,1.));
#1494=AXIS2_PLACEMENT_3D('',#1491,#1492,#1493);
#1495=CIRCLE('',#1494,12.75);
#1496=CARTESIAN_POINT('',(12.75,13.5,-71.5));
#1497=VERTEX_POINT('',#1496);
#1498=EDGE_CURVE('E696',#1473,#1497,#1495,.T.);
#1499=ORIENTED_EDGE('',*,*,#1498,.T.);
#1500=DIRECTION('',(0.,-1.,0.));
#1501=VECTOR('',#1500,1.);
#1502=CARTESIAN_POINT('',(12.75,14.,-71.5));
#1503=LINE('',#1502,#1501);
#1504=CARTESIAN_POINT('',(12.75,14.,-71.5));
#1505=VERTEX_POINT('',#1504);
#1506=EDGE_CURVE('E470',#1505,#1497,#1503,.T.);
#1507=ORIENTED_EDGE('',*,*,#1506,.F.);
#1508=CARTESIAN_POINT('',(0.,14.,-71.5));
#1509=DIRECTION('',(0.,-1.,0.));
#1510=DIRECTION('',(0.,0.,-1.));
#1511=AXIS2_PLACEMENT_3D('',#1508,#1509,#1510);
#1512=CIRCLE('',#1511,12.75);
#1513=EDGE_CURVE('E459',#1505,#1455,#1512,.T.);
#1514=ORIENTED_EDGE('',*,*,#1513,.T.);
#1515=EDGE_LOOP('',(#1490,#1499,#1507,#1514));
#1516=FACE_BOUND('',#1515,.T.);
#1517=ADVANCED_FACE('F1053',(#1516),#1489,.T.);
#1518=CARTESIAN_POINT('',(12.75,14.,-82.5));
#1519=DIRECTION('',(1.,0.,0.));
#1520=DIRECTION('',(0.,0.,-1.));
#1521=AXIS2_PLACEMENT_3D('',#1518,#1519,#1520);
#1522=PLANE('',#1521);
#1523=DIRECTION('',(0.,0.,1.));
#1524=VECTOR('',#1523,1.);
#1525=CARTESIAN_POINT('',(12.75,13.5,-82.5));
#1526=LINE('',#1525,#1524);
#1527=CARTESIAN_POINT('',(12.75,13.5,-81.));
#1528=VERTEX_POINT('',#1527);
#1529=EDGE_CURVE('E646',#1497,#1528,#1526,.F.);
#1530=ORIENTED_EDGE('',*,*,#1529,.T.);
#1531=DIRECTION('',(0.,-1.,0.));
#1532=VECTOR('',#1531,1.);
#1533=CARTESIAN_POINT('',(12.75,14.,-81.));
#1534=LINE('',#1533,#1532);
#1535=CARTESIAN_POINT('',(12.75,14.,-81.));
#1536=VERTEX_POINT('',#1535);
#1537=EDGE_CURVE('E648',#1528,#1536,#1534,.F.);
#1538=ORIENTED_EDGE('',*,*,#1537,.T.);
#1539=DIRECTION('',(0.,0.,1.));
#1540=VECTOR('',#1539,1.);
#1541=CARTESIAN_POINT('',(12.75,14.,-82.5));
#1542=LINE('',#1541,#1540);
#1543=EDGE_CURVE('E462',#1536,#1505,#1542,.T.);
#1544=ORIENTED_EDGE('',*,*,#1543,.T.);
#1545=ORIENTED_EDGE('',*,*,#1506,.T.);
#1546=EDGE_LOOP('',(#1530,#1538,#1544,#1545));
#1547=FACE_BOUND('',#1546,.T.);
#1548=ADVANCED_FACE('F1057',(#1547),#1522,.T.);
#1549=CARTESIAN_POINT('',(0.,14.,-71.5));
#1550=DIRECTION('',(0.,1.,0.));
#1551=DIRECTION('',(0.,0.,-1.));
#1552=AXIS2_PLACEMENT_3D('',#1549,#1550,#1551);
#1553=PLANE('',#1552);
#1554=ORIENTED_EDGE('',*,*,#287,.F.);
#1555=CARTESIAN_POINT('',(-11.25,14.,-81.));
#1556=DIRECTION('',(0.,1.,0.));
#1557=DIRECTION('',(0.,0.,1.));
#1558=AXIS2_PLACEMENT_3D('',#1555,#1556,#1557);
#1559=CIRCLE('',#1558,1.5);
#1560=EDGE_CURVE('E637',#278,#1457,#1559,.T.);
#1561=ORIENTED_EDGE('',*,*,#1560,.T.);
#1562=ORIENTED_EDGE('',*,*,#1458,.F.);
#1563=ORIENTED_EDGE('',*,*,#1513,.F.);
#1564=ORIENTED_EDGE('',*,*,#1543,.F.);
#1565=CARTESIAN_POINT('',(11.25,14.,-81.));
#1566=DIRECTION('',(0.,1.,0.));
#1567=DIRECTION('',(0.,0.,1.));
#1568=AXIS2_PLACEMENT_3D('',#1565,#1566,#1567);
#1569=CIRCLE('',#1568,1.5);
#1570=EDGE_CURVE('E635',#1536,#329,#1569,.T.);
#1571=ORIENTED_EDGE('',*,*,#1570,.T.);
#1572=ORIENTED_EDGE('',*,*,#330,.F.);
#1573=ORIENTED_EDGE('',*,*,#1420,.F.);
#1574=ORIENTED_EDGE('',*,*,#1438,.F.);
#1575=ORIENTED_EDGE('',*,*,#1391,.F.);
#1576=EDGE_LOOP('',(#1554,#1561,#1562,#1563,#1564,#1571,#1572,#1573,#1574,#1575));
#1577=FACE_BOUND('',#1576,.T.);
#1578=ADVANCED_FACE('F1061',(#1577),#1553,.T.);
#1579=CARTESIAN_POINT('',(25.45,20.,38.));
#1580=DIRECTION('',(1.,0.,0.));
#1581=DIRECTION('',(0.,0.,-1.));
#1582=AXIS2_PLACEMENT_3D('',#1579,#1580,#1581);
#1583=CONICAL_SURFACE('',#1582,3.,1.02974425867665);
#1584=CARTESIAN_POINT('',(23.6474181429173,20.,38.));
#1585=VERTEX_POINT('',#1584);
#1586=VERTEX_LOOP('',#1585);
#1587=FACE_BOUND('',#1586,.T.);
#1588=CARTESIAN_POINT('',(25.45,20.,38.));
#1589=DIRECTION('',(1.,0.,0.));
#1590=DIRECTION('',(0.,0.,-1.));
#1591=AXIS2_PLACEMENT_3D('',#1588,#1589,#1590);
#1592=CIRCLE('',#1591,3.);
#1593=CARTESIAN_POINT('',(25.45,20.,35.));
#1594=VERTEX_POINT('',#1593);
#1595=EDGE_CURVE('E445',#1594,#1594,#1592,.T.);
#1596=ORIENTED_EDGE('',*,*,#1595,.T.);
#1597=EDGE_LOOP('',(#1596));
#1598=FACE_BOUND('',#1597,.T.);
#1599=ADVANCED_FACE('F1065',(#1587,#1598),#1583,.F.);
#1600=CARTESIAN_POINT('',(44.45,20.,38.));
#1601=DIRECTION('',(1.,0.,0.));
#1602=DIRECTION('',(0.,0.,-1.));
#1603=AXIS2_PLACEMENT_3D('',#1600,#1601,#1602);
#1604=CYLINDRICAL_SURFACE('',#1603,3.);
#1605=ORIENTED_EDGE('',*,*,#1595,.F.);
#1606=EDGE_LOOP('',(#1605));
#1607=FACE_BOUND('',#1606,.T.);
#1608=ORIENTED_EDGE('',*,*,#219,.T.);
#1609=EDGE_LOOP('',(#1608));
#1610=FACE_BOUND('',#1609,.T.);
#1611=ADVANCED_FACE('F1069',(#1607,#1610),#1604,.F.);
#1612=CARTESIAN_POINT('',(29.95,16.5,23.75));
#1613=DIRECTION('',(1.,0.,0.));
#1614=DIRECTION('',(0.,0.,-1.));
#1615=AXIS2_PLACEMENT_3D('',#1612,#1613,#1614);
#1616=CYLINDRICAL_SURFACE('',#1615,1.5);
#1617=CARTESIAN_POINT('',(29.95,16.5,23.75));
#1618=DIRECTION('',(1.,0.,0.));
#1619=DIRECTION('',(0.,0.,-1.));
#1620=AXIS2_PLACEMENT_3D('',#1617,#1618,#1619);
#1621=CIRCLE('',#1620,1.5);
#1622=CARTESIAN_POINT('',(29.95,16.5,22.25));
#1623=VERTEX_POINT('',#1622);
#1624=EDGE_CURVE('E437',#1623,#1623,#1621,.T.);
#1625=CARTESIAN_POINT('',(29.95,16.5,22.25));
#1626=CARTESIAN_POINT('',(30.1010416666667,16.5,22.25));
#1627=CARTESIAN_POINT('',(30.2520833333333,16.5,22.25));
#1628=CARTESIAN_POINT('',(30.5541666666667,16.5,22.25));
#1629=CARTESIAN_POINT('',(30.7052083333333,16.5,22.25));
#1630=CARTESIAN_POINT('',(31.0072916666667,16.5,22.25));
#1631=CARTESIAN_POINT('',(31.1583333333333,16.5,22.25));
#1632=CARTESIAN_POINT('',(31.4604166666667,16.5,22.25));
#1633=CARTESIAN_POINT('',(31.6114583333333,16.5,22.25));
#1634=CARTESIAN_POINT('',(31.9135416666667,16.5,22.25));
#1635=CARTESIAN_POINT('',(32.0645833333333,16.5,22.25));
#1636=CARTESIAN_POINT('',(32.3666666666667,16.5,22.25));
#1637=CARTESIAN_POINT('',(32.5177083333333,16.5,22.25));
#1638=CARTESIAN_POINT('',(32.8197916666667,16.5,22.25));
#1639=CARTESIAN_POINT('',(32.9708333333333,16.5,22.25));
#1640=CARTESIAN_POINT('',(33.2729166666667,16.5,22.25));
#1641=CARTESIAN_POINT('',(33.4239583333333,16.5,22.25));
#1642=CARTESIAN_POINT('',(33.7260416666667,16.5,22.25));
#1643=CARTESIAN_POINT('',(33.8770833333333,16.5,22.25));
#1644=CARTESIAN_POINT('',(34.1791666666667,16.5,22.25));
#1645=CARTESIAN_POINT('',(34.3302083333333,16.5,22.25));
#1646=CARTESIAN_POINT('',(34.6322916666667,16.5,22.25));
#1647=CARTESIAN_POINT('',(34.7833333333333,16.5,22.25));
#1648=CARTESIAN_POINT('',(35.0854166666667,16.5,22.25));
#1649=CARTESIAN_POINT('',(35.2364583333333,16.5,22.25));
#1650=CARTESIAN_POINT('',(35.5385416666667,16.5,22.25));
#1651=CARTESIAN_POINT('',(35.6895833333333,16.5,22.25));
#1652=CARTESIAN_POINT('',(35.9916666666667,16.5,22.25));
#1653=CARTESIAN_POINT('',(36.1427083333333,16.5,22.25));
#1654=CARTESIAN_POINT('',(36.4447916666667,16.5,22.25));
#1655=CARTESIAN_POINT('',(36.5958333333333,16.5,22.25));
#1656=CARTESIAN_POINT('',(36.8979166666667,16.5,22.25));
#1657=CARTESIAN_POINT('',(37.0489583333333,16.5,22.25));
#1658=CARTESIAN_POINT('',(37.3510416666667,16.5,22.25));
#1659=CARTESIAN_POINT('',(37.5020833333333,16.5,22.25));
#1660=CARTESIAN_POINT('',(37.8041666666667,16.5,22.25));
#1661=CARTESIAN_POINT('',(37.9552083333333,16.5,22.25));
#1662=CARTESIAN_POINT('',(38.2572916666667,16.5,22.25));
#1663=CARTESIAN_POINT('',(38.4083333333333,16.5,22.25));
#1664=CARTESIAN_POINT('',(38.7104166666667,16.5,22.25));
#1665=CARTESIAN_POINT('',(38.8614583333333,16.5,22.25));
#1666=CARTESIAN_POINT('',(39.1635416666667,16.5,22.25));
#1667=CARTESIAN_POINT('',(39.3145833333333,16.5,22.25));
#1668=CARTESIAN_POINT('',(39.6166666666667,16.5,22.25));
#1669=CARTESIAN_POINT('',(39.7677083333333,16.5,22.25));
#1670=CARTESIAN_POINT('',(40.0697916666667,16.5,22.25));
#1671=CARTESIAN_POINT('',(40.2208333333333,16.5,22.25));
#1672=CARTESIAN_POINT('',(40.5229166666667,16.5,22.25));
#1673=CARTESIAN_POINT('',(40.6739583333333,16.5,22.25));
#1674=CARTESIAN_POINT('',(40.9760416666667,16.5,22.25));
#1675=CARTESIAN_POINT('',(41.1270833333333,16.5,22.25));
#1676=CARTESIAN_POINT('',(41.4291666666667,16.5,22.25));
#1677=CARTESIAN_POINT('',(41.5802083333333,16.5,22.25));
#1678=CARTESIAN_POINT('',(41.8822916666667,16.5,22.25));
#1679=CARTESIAN_POINT('',(42.0333333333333,16.5,22.25));
#1680=CARTESIAN_POINT('',(42.3354166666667,16.5,22.25));
#1681=CARTESIAN_POINT('',(42.4864583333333,16.5,22.25));
#1682=CARTESIAN_POINT('',(42.7885416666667,16.5,22.25));
#1683=CARTESIAN_POINT('',(42.9395833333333,16.5,22.25));
#1684=CARTESIAN_POINT('',(43.2416666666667,16.5,22.25));
#1685=CARTESIAN_POINT('',(43.3927083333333,16.5,22.25));
#1686=CARTESIAN_POINT('',(43.6947916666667,16.5,22.25));
#1687=CARTESIAN_POINT('',(43.8458333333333,16.5,22.25));
#1688=CARTESIAN_POINT('',(44.1479166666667,16.5,22.25));
#1689=CARTESIAN_POINT('',(44.2989583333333,16.5,22.25));
#1690=CARTESIAN_POINT('',(44.45,16.5,22.25));
#1691=B_SPLINE_CURVE_WITH_KNOTS('',3,(#1625,#1626,#1627,#1628,#1629,#1630,#1631,#1632,#1633,
#1634,#1635,#1636,#1637,#1638,#1639,#1640,#1641,#1642,#1643,#1644,#1645,#1646,#1647,#1648,#1649,
#1650,#1651,#1652,#1653,#1654,#1655,#1656,#1657,#1658,#1659,#1660,#1661,#1662,#1663,#1664,#1665,
#1666,#1667,#1668,#1669,#1670,#1671,#1672,#1673,#1674,#1675,#1676,#1677,#1678,#1679,#1680,#1681,
#1682,#1683,#1684,#1685,#1686,#1687,#1688,#1689,#1690),.UNSPECIFIED.,.F.,.F.,(4,2,2,2,2,2,2,2,2,
2,2,2,2,2,2,2,2,2,2,2,2,2,2,2,2,2,2,2,2,2,2,2,4),(0.,0.453125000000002,0.906250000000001,
1.359375,1.8125,2.265625,2.71875,3.171875,3.625,4.078125,4.53125,4.984375,5.4375,5.890625,
6.34375,6.796875,7.25,7.703125,8.15625,8.609375,9.0625,9.515625,9.96875,10.421875,10.875,
11.328125,11.78125,12.234375,12.6875,13.140625,13.59375,14.046875,14.5),.UNSPECIFIED.);
#1692=EDGE_CURVE('BSEAM1073',#1623,#229,#1691,.T.);
#1693=ORIENTED_EDGE('',*,*,#1624,.F.);
#1694=ORIENTED_EDGE('',*,*,#230,.T.);
#1695=ORIENTED_EDGE('',*,*,#1692,.T.);
#1696=ORIENTED_EDGE('',*,*,#1692,.F.);
#1697=EDGE_LOOP('',(#1693,#1695,#1694,#1696));
#1698=FACE_BOUND('',#1697,.T.);
#1699=ADVANCED_FACE('F1073',(#1698),#1616,.F.);
#1700=CARTESIAN_POINT('',(29.95,16.5,23.75));
#1701=DIRECTION('',(1.,0.,0.));
#1702=DIRECTION('',(0.,0.,-1.));
#1703=AXIS2_PLACEMENT_3D('',#1700,#1701,#1702);
#1704=PLANE('',#1703);
#1705=ORIENTED_EDGE('',*,*,#1624,.T.);
#1706=EDGE_LOOP('',(#1705));
#1707=FACE_BOUND('',#1706,.T.);
#1708=ADVANCED_FACE('F1077',(#1707),#1704,.T.);
#1709=CARTESIAN_POINT('',(25.45,20.,-38.));
#1710=DIRECTION('',(1.,0.,0.));
#1711=DIRECTION('',(0.,0.,-1.));
#1712=AXIS2_PLACEMENT_3D('',#1709,#1710,#1711);
#1713=CONICAL_SURFACE('',#1712,3.,1.02974425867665);
#1714=CARTESIAN_POINT('',(23.6474181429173,20.,-38.));
#1715=VERTEX_POINT('',#1714);
#1716=VERTEX_LOOP('',#1715);
#1717=FACE_BOUND('',#1716,.T.);
#1718=CARTESIAN_POINT('',(25.45,20.,-38.));
#1719=DIRECTION('',(1.,0.,0.));
#1720=DIRECTION('',(0.,0.,-1.));
#1721=AXIS2_PLACEMENT_3D('',#1718,#1719,#1720);
#1722=CIRCLE('',#1721,3.);
#1723=CARTESIAN_POINT('',(25.45,20.,-41.));
#1724=VERTEX_POINT('',#1723);
#1725=EDGE_CURVE('E432',#1724,#1724,#1722,.T.);
#1726=ORIENTED_EDGE('',*,*,#1725,.T.);
#1727=EDGE_LOOP('',(#1726));
#1728=FACE_BOUND('',#1727,.T.);
#1729=ADVANCED_FACE('F1081',(#1717,#1728),#1713,.F.);
#1730=CARTESIAN_POINT('',(44.45,20.,-38.));
#1731=DIRECTION('',(1.,0.,0.));
#1732=DIRECTION('',(0.,0.,-1.));
#1733=AXIS2_PLACEMENT_3D('',#1730,#1731,#1732);
#1734=CYLINDRICAL_SURFACE('',#1733,3.);
#1735=ORIENTED_EDGE('',*,*,#1725,.F.);
#1736=EDGE_LOOP('',(#1735));
#1737=FACE_BOUND('',#1736,.T.);
#1738=ORIENTED_EDGE('',*,*,#241,.T.);
#1739=EDGE_LOOP('',(#1738));
#1740=FACE_BOUND('',#1739,.T.);
#1741=ADVANCED_FACE('F1085',(#1737,#1740),#1734,.F.);
#1742=CARTESIAN_POINT('',(-32.5,12.,-72.5));
#1743=DIRECTION('',(0.,-1.,0.));
#1744=DIRECTION('',(0.,0.,-1.));
#1745=AXIS2_PLACEMENT_3D('',#1742,#1743,#1744);
#1746=CYLINDRICAL_SURFACE('',#1745,10.);
#1747=ORIENTED_EDGE('',*,*,#773,.F.);
#1748=CARTESIAN_POINT('',(-32.5,10.5,-72.5));
#1749=DIRECTION('',(0.,1.,0.));
#1750=DIRECTION('',(0.,0.,1.));
#1751=AXIS2_PLACEMENT_3D('',#1748,#1749,#1750);
#1752=CIRCLE('',#1751,10.);
#1753=EDGE_CURVE('E703',#766,#310,#1752,.F.);
#1754=ORIENTED_EDGE('',*,*,#1753,.T.);
#1755=ORIENTED_EDGE('',*,*,#311,.F.);
#1756=ORIENTED_EDGE('',*,*,#489,.F.);
#1757=EDGE_LOOP('',(#1747,#1754,#1755,#1756));
#1758=FACE_BOUND('',#1757,.T.);
#1759=ADVANCED_FACE('F927',(#1758),#1746,.T.);
#1760=CARTESIAN_POINT('',(32.5,12.,-72.5));
#1761=DIRECTION('',(0.,-1.,0.));
#1762=DIRECTION('',(0.,0.,-1.));
#1763=AXIS2_PLACEMENT_3D('',#1760,#1761,#1762);
#1764=CYLINDRICAL_SURFACE('',#1763,10.);
#1765=ORIENTED_EDGE('',*,*,#363,.F.);
#1766=CARTESIAN_POINT('',(32.5,10.5,-72.5));
#1767=DIRECTION('',(0.,1.,0.));
#1768=DIRECTION('',(0.,0.,1.));
#1769=AXIS2_PLACEMENT_3D('',#1766,#1767,#1768);
#1770=CIRCLE('',#1769,10.);
#1771=EDGE_CURVE('E705',#354,#869,#1770,.F.);
#1772=ORIENTED_EDGE('',*,*,#1771,.T.);
#1773=ORIENTED_EDGE('',*,*,#870,.F.);
#1774=ORIENTED_EDGE('',*,*,#523,.F.);
#1775=EDGE_LOOP('',(#1765,#1772,#1773,#1774));
#1776=FACE_BOUND('',#1775,.T.);
#1777=ADVANCED_FACE('F1455',(#1776),#1764,.T.);
#1778=CARTESIAN_POINT('',(32.5,12.,72.5));
#1779=DIRECTION('',(0.,-1.,0.));
#1780=DIRECTION('',(0.,0.,-1.));
#1781=AXIS2_PLACEMENT_3D('',#1778,#1779,#1780);
#1782=CYLINDRICAL_SURFACE('',#1781,10.);
#1783=ORIENTED_EDGE('',*,*,#930,.F.);
#1784=CARTESIAN_POINT('',(32.5,10.5,72.5));
#1785=DIRECTION('',(0.,1.,0.));
#1786=DIRECTION('',(0.,0.,1.));
#1787=AXIS2_PLACEMENT_3D('',#1784,#1785,#1786);
#1788=CIRCLE('',#1787,10.);
#1789=EDGE_CURVE('E730',#923,#847,#1788,.F.);
#1790=ORIENTED_EDGE('',*,*,#1789,.T.);
#1791=ORIENTED_EDGE('',*,*,#848,.F.);
#1792=ORIENTED_EDGE('',*,*,#540,.F.);
#1793=EDGE_LOOP('',(#1783,#1790,#1791,#1792));
#1794=FACE_BOUND('',#1793,.T.);
#1795=ADVANCED_FACE('F1447',(#1794),#1782,.T.);
#1796=CARTESIAN_POINT('',(-32.5,12.,72.5));
#1797=DIRECTION('',(0.,-1.,0.));
#1798=DIRECTION('',(0.,0.,-1.));
#1799=AXIS2_PLACEMENT_3D('',#1796,#1797,#1798);
#1800=CYLINDRICAL_SURFACE('',#1799,10.);
#1801=ORIENTED_EDGE('',*,*,#719,.F.);
#1802=CARTESIAN_POINT('',(-32.5,10.5,72.5));
#1803=DIRECTION('',(0.,1.,0.));
#1804=DIRECTION('',(0.,0.,1.));
#1805=AXIS2_PLACEMENT_3D('',#1802,#1803,#1804);
#1806=CIRCLE('',#1805,10.);
#1807=EDGE_CURVE('E726',#712,#781,#1806,.F.);
#1808=ORIENTED_EDGE('',*,*,#1807,.T.);
#1809=ORIENTED_EDGE('',*,*,#782,.F.);
#1810=ORIENTED_EDGE('',*,*,#584,.F.);
#1811=EDGE_LOOP('',(#1801,#1808,#1809,#1810));
#1812=FACE_BOUND('',#1811,.T.);
#1813=ADVANCED_FACE('F1439',(#1812),#1800,.T.);
#1814=CARTESIAN_POINT('',(41.,10.5,0.));
#1815=DIRECTION('',(0.,0.,1.));
#1816=DIRECTION('',(1.,0.,0.));
#1817=AXIS2_PLACEMENT_3D('',#1814,#1815,#1816);
#1818=CYLINDRICAL_SURFACE('',#1817,1.5);
#1819=ORIENTED_EDGE('',*,*,#407,.F.);
#1820=CARTESIAN_POINT('',(41.,10.5,-45.95));
#1821=DIRECTION('',(0.,0.,1.));
#1822=DIRECTION('',(1.,0.,0.));
#1823=AXIS2_PLACEMENT_3D('',#1820,#1821,#1822);
#1824=CIRCLE('',#1823,1.5);
#1825=EDGE_CURVE('E843',#398,#877,#1824,.F.);
#1826=ORIENTED_EDGE('',*,*,#1825,.T.);
#1827=ORIENTED_EDGE('',*,*,#878,.F.);
#1828=CARTESIAN_POINT('',(41.,10.5,-72.5));
#1829=DIRECTION('',(0.,0.,-1.));
#1830=DIRECTION('',(-1.,0.,0.));
#1831=AXIS2_PLACEMENT_3D('',#1828,#1829,#1830);
#1832=CIRCLE('',#1831,1.5);
#1833=EDGE_CURVE('E433',#406,#869,#1832,.T.);
#1834=ORIENTED_EDGE('',*,*,#1833,.F.);
#1835=EDGE_LOOP('',(#1819,#1826,#1827,#1834));
#1836=FACE_BOUND('',#1835,.T.);
#1837=ADVANCED_FACE('F1431',(#1836),#1818,.T.);
#1838=CARTESIAN_POINT('',(32.5,10.5,-72.5));
#1839=DIRECTION('',(0.,1.,0.));
#1840=DIRECTION('',(0.,0.,1.));
#1841=AXIS2_PLACEMENT_3D('',#1838,#1839,#1840);
#1842=TOROIDAL_SURFACE('',#1841,8.5,1.5);
#1843=ORIENTED_EDGE('',*,*,#1833,.T.);
#1844=ORIENTED_EDGE('',*,*,#1771,.F.);
#1845=CARTESIAN_POINT('',(32.5,10.5,-81.));
#1846=DIRECTION('',(-1.,0.,0.));
#1847=DIRECTION('',(0.,0.,1.));
#1848=AXIS2_PLACEMENT_3D('',#1845,#1846,#1847);
#1849=CIRCLE('',#1848,1.5);
#1850=EDGE_CURVE('E786',#415,#354,#1849,.T.);
#1851=ORIENTED_EDGE('',*,*,#1850,.F.);
#1852=ORIENTED_EDGE('',*,*,#416,.F.);
#1853=EDGE_LOOP('',(#1843,#1844,#1851,#1852));
#1854=FACE_BOUND('',#1853,.T.);
#1855=ADVANCED_FACE('F1423',(#1854),#1842,.T.);
#1856=CARTESIAN_POINT('',(11.25,12.,-81.));
#1857=DIRECTION('',(0.,1.,0.));
#1858=DIRECTION('',(0.,0.,1.));
#1859=AXIS2_PLACEMENT_3D('',#1856,#1857,#1858);
#1860=CYLINDRICAL_SURFACE('',#1859,1.5);
#1861=ORIENTED_EDGE('',*,*,#1570,.F.);
#1862=ORIENTED_EDGE('',*,*,#1537,.F.);
#1863=CARTESIAN_POINT('',(11.25,13.5,-81.));
#1864=DIRECTION('',(0.,-1.,0.));
#1865=DIRECTION('',(0.,0.,-1.));
#1866=AXIS2_PLACEMENT_3D('',#1863,#1864,#1865);
#1867=CIRCLE('',#1866,1.5);
#1868=EDGE_CURVE('E783',#337,#1528,#1867,.T.);
#1869=ORIENTED_EDGE('',*,*,#1868,.F.);
#1870=ORIENTED_EDGE('',*,*,#338,.F.);
#1871=EDGE_LOOP('',(#1861,#1862,#1869,#1870));
#1872=FACE_BOUND('',#1871,.T.);
#1873=ADVANCED_FACE('F1415',(#1872),#1860,.T.);
#1874=CARTESIAN_POINT('',(0.,10.5,-81.));
#1875=DIRECTION('',(1.,0.,0.));
#1876=DIRECTION('',(0.,0.,-1.));
#1877=AXIS2_PLACEMENT_3D('',#1874,#1875,#1876);
#1878=CYLINDRICAL_SURFACE('',#1877,1.5);
#1879=ORIENTED_EDGE('',*,*,#1850,.T.);
#1880=ORIENTED_EDGE('',*,*,#355,.F.);
#1881=CARTESIAN_POINT('',(14.25,10.5,-81.));
#1882=DIRECTION('',(-1.,0.,0.));
#1883=DIRECTION('',(0.,0.,1.));
#1884=AXIS2_PLACEMENT_3D('',#1881,#1882,#1883);
#1885=CIRCLE('',#1884,1.5);
#1886=EDGE_CURVE('E780',#423,#346,#1885,.T.);
#1887=ORIENTED_EDGE('',*,*,#1886,.F.);
#1888=ORIENTED_EDGE('',*,*,#424,.F.);
#1889=EDGE_LOOP('',(#1879,#1880,#1887,#1888));
#1890=FACE_BOUND('',#1889,.T.);
#1891=ADVANCED_FACE('F1407',(#1890),#1878,.T.);
#1892=CARTESIAN_POINT('',(14.25,13.5,-81.));
#1893=DIRECTION('',(0.,0.,1.));
#1894=DIRECTION('',(1.,0.,0.));
#1895=AXIS2_PLACEMENT_3D('',#1892,#1893,#1894);
#1896=TOROIDAL_SURFACE('',#1895,3.,1.5);
#1897=ORIENTED_EDGE('',*,*,#347,.T.);
#1898=ORIENTED_EDGE('',*,*,#1868,.T.);
#1899=CARTESIAN_POINT('',(14.25,13.5,-81.));
#1900=DIRECTION('',(0.,0.,1.));
#1901=DIRECTION('',(1.,0.,0.));
#1902=AXIS2_PLACEMENT_3D('',#1899,#1900,#1901);
#1903=CIRCLE('',#1902,1.5);
#1904=EDGE_CURVE('E777',#423,#1528,#1903,.F.);
#1905=ORIENTED_EDGE('',*,*,#1904,.F.);
#1906=ORIENTED_EDGE('',*,*,#1886,.T.);
#1907=EDGE_LOOP('',(#1897,#1898,#1905,#1906));
#1908=FACE_BOUND('',#1907,.T.);
#1909=ADVANCED_FACE('F1399',(#1908),#1896,.T.);
#1910=CARTESIAN_POINT('',(14.25,13.5,0.));
#1911=DIRECTION('',(0.,0.,-1.));
#1912=DIRECTION('',(-1.,0.,0.));
#1913=AXIS2_PLACEMENT_3D('',#1910,#1911,#1912);
#1914=CYLINDRICAL_SURFACE('',#1913,1.5);
#1915=ORIENTED_EDGE('',*,*,#1904,.T.);
#1916=ORIENTED_EDGE('',*,*,#1529,.F.);
#1917=CARTESIAN_POINT('',(14.25,13.5,-71.5));
#1918=DIRECTION('',(0.,0.,-1.));
#1919=DIRECTION('',(-1.,0.,0.));
#1920=AXIS2_PLACEMENT_3D('',#1917,#1918,#1919);
#1921=CIRCLE('',#1920,1.5);
#1922=EDGE_CURVE('E774',#431,#1497,#1921,.T.);
#1923=ORIENTED_EDGE('',*,*,#1922,.F.);
#1924=ORIENTED_EDGE('',*,*,#432,.F.);
#1925=EDGE_LOOP('',(#1915,#1916,#1923,#1924));
#1926=FACE_BOUND('',#1925,.T.);
#1927=ADVANCED_FACE('F1391',(#1926),#1914,.F.);
#1928=CARTESIAN_POINT('',(-41.,10.5,0.));
#1929=DIRECTION('',(0.,0.,-1.));
#1930=DIRECTION('',(-1.,0.,0.));
#1931=AXIS2_PLACEMENT_3D('',#1928,#1929,#1930);
#1932=CYLINDRICAL_SURFACE('',#1931,1.5);
#1933=ORIENTED_EDGE('',*,*,#767,.F.);
#1934=CARTESIAN_POINT('',(-41.,10.5,-45.95));
#1935=DIRECTION('',(0.,0.,1.));
#1936=DIRECTION('',(1.,0.,0.));
#1937=AXIS2_PLACEMENT_3D('',#1934,#1935,#1936);
#1938=CIRCLE('',#1937,1.5);
#1939=EDGE_CURVE('E845',#758,#390,#1938,.F.);
#1940=ORIENTED_EDGE('',*,*,#1939,.T.);
#1941=ORIENTED_EDGE('',*,*,#391,.F.);
#1942=CARTESIAN_POINT('',(-41.,10.5,-72.5));
#1943=DIRECTION('',(0.,0.,-1.));
#1944=DIRECTION('',(-1.,0.,0.));
#1945=AXIS2_PLACEMENT_3D('',#1942,#1943,#1944);
#1946=CIRCLE('',#1945,1.5);
#1947=EDGE_CURVE('E771',#766,#388,#1946,.T.);
#1948=ORIENTED_EDGE('',*,*,#1947,.F.);
#1949=EDGE_LOOP('',(#1933,#1940,#1941,#1948));
#1950=FACE_BOUND('',#1949,.T.);
#1951=ADVANCED_FACE('F1383',(#1950),#1932,.T.);
#1952=CARTESIAN_POINT('',(0.,13.5,-71.5));
#1953=DIRECTION('',(0.,1.,0.));
#1954=DIRECTION('',(0.,0.,1.));
#1955=AXIS2_PLACEMENT_3D('',#1952,#1953,#1954);
#1956=TOROIDAL_SURFACE('',#1955,14.25,1.5);
#1957=ORIENTED_EDGE('',*,*,#1922,.T.);
#1958=ORIENTED_EDGE('',*,*,#1498,.F.);
#1959=CARTESIAN_POINT('',(-14.25,13.5,-71.5));
#1960=DIRECTION('',(0.,0.,1.));
#1961=DIRECTION('',(1.,0.,0.));
#1962=AXIS2_PLACEMENT_3D('',#1959,#1960,#1961);
#1963=CIRCLE('',#1962,1.5);
#1964=EDGE_CURVE('E768',#440,#1473,#1963,.T.);
#1965=ORIENTED_EDGE('',*,*,#1964,.F.);
#1966=ORIENTED_EDGE('',*,*,#441,.F.);
#1967=EDGE_LOOP('',(#1957,#1958,#1965,#1966));
#1968=FACE_BOUND('',#1967,.T.);
#1969=ADVANCED_FACE('F1375',(#1968),#1956,.F.);
#1970=CARTESIAN_POINT('',(-32.5,10.5,-72.5));
#1971=DIRECTION('',(0.,1.,0.));
#1972=DIRECTION('',(0.,0.,1.));
#1973=AXIS2_PLACEMENT_3D('',#1970,#1971,#1972);
#1974=TOROIDAL_SURFACE('',#1973,8.5,1.5);
#1975=ORIENTED_EDGE('',*,*,#1947,.T.);
#1976=ORIENTED_EDGE('',*,*,#464,.F.);
#1977=CARTESIAN_POINT('',(-32.5,10.5,-81.));
#1978=DIRECTION('',(1.,0.,0.));
#1979=DIRECTION('',(0.,0.,-1.));
#1980=AXIS2_PLACEMENT_3D('',#1977,#1978,#1979);
#1981=CIRCLE('',#1980,1.5);
#1982=EDGE_CURVE('E765',#310,#456,#1981,.T.);
#1983=ORIENTED_EDGE('',*,*,#1982,.F.);
#1984=ORIENTED_EDGE('',*,*,#1753,.F.);
#1985=EDGE_LOOP('',(#1975,#1976,#1983,#1984));
#1986=FACE_BOUND('',#1985,.T.);
#1987=ADVANCED_FACE('F1367',(#1986),#1974,.T.);
#1988=CARTESIAN_POINT('',(-14.25,13.5,0.));
#1989=DIRECTION('',(0.,0.,1.));
#1990=DIRECTION('',(1.,0.,0.));
#1991=AXIS2_PLACEMENT_3D('',#1988,#1989,#1990);
#1992=CYLINDRICAL_SURFACE('',#1991,1.5);
#1993=ORIENTED_EDGE('',*,*,#1964,.T.);
#1994=ORIENTED_EDGE('',*,*,#1474,.F.);
#1995=CARTESIAN_POINT('',(-14.25,13.5,-81.));
#1996=DIRECTION('',(0.,0.,1.));
#1997=DIRECTION('',(1.,0.,0.));
#1998=AXIS2_PLACEMENT_3D('',#1995,#1996,#1997);
#1999=CIRCLE('',#1998,1.5);
#2000=EDGE_CURVE('E762',#448,#1465,#1999,.T.);
#2001=ORIENTED_EDGE('',*,*,#2000,.F.);
#2002=ORIENTED_EDGE('',*,*,#449,.F.);
#2003=EDGE_LOOP('',(#1993,#1994,#2001,#2002));
#2004=FACE_BOUND('',#2003,.T.);
#2005=ADVANCED_FACE('F1359',(#2004),#1992,.F.);
#2006=CARTESIAN_POINT('',(0.,10.5,-81.));
#2007=DIRECTION('',(1.,0.,0.));
#2008=DIRECTION('',(0.,0.,-1.));
#2009=AXIS2_PLACEMENT_3D('',#2006,#2007,#2008);
#2010=CYLINDRICAL_SURFACE('',#2009,1.5);
#2011=ORIENTED_EDGE('',*,*,#1982,.T.);
#2012=ORIENTED_EDGE('',*,*,#457,.F.);
#2013=CARTESIAN_POINT('',(-14.25,10.5,-81.));
#2014=DIRECTION('',(1.,0.,0.));
#2015=DIRECTION('',(0.,0.,-1.));
#2016=AXIS2_PLACEMENT_3D('',#2013,#2014,#2015);
#2017=CIRCLE('',#2016,1.5);
#2018=EDGE_CURVE('E758',#270,#448,#2017,.T.);
#2019=ORIENTED_EDGE('',*,*,#2018,.F.);
#2020=ORIENTED_EDGE('',*,*,#317,.F.);
#2021=EDGE_LOOP('',(#2011,#2012,#2019,#2020));
#2022=FACE_BOUND('',#2021,.T.);
#2023=ADVANCED_FACE('F1351',(#2022),#2010,.T.);
#2024=CARTESIAN_POINT('',(-14.25,13.5,-81.));
#2025=DIRECTION('',(0.,0.,1.));
#2026=DIRECTION('',(1.,0.,0.));
#2027=AXIS2_PLACEMENT_3D('',#2024,#2025,#2026);
#2028=TOROIDAL_SURFACE('',#2027,3.,1.5);
#2029=ORIENTED_EDGE('',*,*,#2018,.T.);
#2030=ORIENTED_EDGE('',*,*,#2000,.T.);
#2031=CARTESIAN_POINT('',(-11.25,13.5,-81.));
#2032=DIRECTION('',(0.,-1.,0.));
#2033=DIRECTION('',(0.,0.,-1.));
#2034=AXIS2_PLACEMENT_3D('',#2031,#2032,#2033);
#2035=CIRCLE('',#2034,1.5);
#2036=EDGE_CURVE('E756',#268,#1465,#2035,.F.);
#2037=ORIENTED_EDGE('',*,*,#2036,.F.);
#2038=ORIENTED_EDGE('',*,*,#271,.T.);
#2039=EDGE_LOOP('',(#2029,#2030,#2037,#2038));
#2040=FACE_BOUND('',#2039,.T.);
#2041=ADVANCED_FACE('F1343',(#2040),#2028,.T.);
#2042=CARTESIAN_POINT('',(-11.25,14.,-81.));
#2043=DIRECTION('',(0.,1.,0.));
#2044=DIRECTION('',(0.,0.,1.));
#2045=AXIS2_PLACEMENT_3D('',#2042,#2043,#2044);
#2046=CYLINDRICAL_SURFACE('',#2045,1.5);
#2047=ORIENTED_EDGE('',*,*,#1560,.F.);
#2048=ORIENTED_EDGE('',*,*,#279,.F.);
#2049=ORIENTED_EDGE('',*,*,#2036,.T.);
#2050=ORIENTED_EDGE('',*,*,#1466,.F.);
#2051=EDGE_LOOP('',(#2047,#2048,#2049,#2050));
#2052=FACE_BOUND('',#2051,.T.);
#2053=ADVANCED_FACE('F1335',(#2052),#2046,.T.);
#2054=CARTESIAN_POINT('',(41.,10.5,0.));
#2055=DIRECTION('',(0.,0.,1.));
#2056=DIRECTION('',(1.,0.,0.));
#2057=AXIS2_PLACEMENT_3D('',#2054,#2055,#2056);
#2058=CYLINDRICAL_SURFACE('',#2057,1.5);
#2059=ORIENTED_EDGE('',*,*,#924,.F.);
#2060=CARTESIAN_POINT('',(41.,10.5,45.95));
#2061=DIRECTION('',(0.,0.,-1.));
#2062=DIRECTION('',(-1.,0.,0.));
#2063=AXIS2_PLACEMENT_3D('',#2060,#2061,#2062);
#2064=CIRCLE('',#2063,1.5);
#2065=EDGE_CURVE('E832',#915,#596,#2064,.F.);
#2066=ORIENTED_EDGE('',*,*,#2065,.T.);
#2067=ORIENTED_EDGE('',*,*,#597,.F.);
#2068=CARTESIAN_POINT('',(41.,10.5,72.5));
#2069=DIRECTION('',(0.,0.,1.));
#2070=DIRECTION('',(1.,0.,0.));
#2071=AXIS2_PLACEMENT_3D('',#2068,#2069,#2070);
#2072=CIRCLE('',#2071,1.5);
#2073=EDGE_CURVE('E759',#923,#594,#2072,.T.);
#2074=ORIENTED_EDGE('',*,*,#2073,.F.);
#2075=EDGE_LOOP('',(#2059,#2066,#2067,#2074));
#2076=FACE_BOUND('',#2075,.T.);
#2077=ADVANCED_FACE('F1327',(#2076),#2058,.T.);
#2078=CARTESIAN_POINT('',(32.5,10.5,72.5));
#2079=DIRECTION('',(0.,1.,0.));
#2080=DIRECTION('',(0.,0.,1.));
#2081=AXIS2_PLACEMENT_3D('',#2078,#2079,#2080);
#2082=TOROIDAL_SURFACE('',#2081,8.5,1.5);
#2083=ORIENTED_EDGE('',*,*,#2073,.T.);
#2084=ORIENTED_EDGE('',*,*,#670,.F.);
#2085=CARTESIAN_POINT('',(32.5,10.5,81.));
#2086=DIRECTION('',(-1.,0.,0.));
#2087=DIRECTION('',(0.,0.,1.));
#2088=AXIS2_PLACEMENT_3D('',#2085,#2086,#2087);
#2089=CIRCLE('',#2088,1.5);
#2090=EDGE_CURVE('E821',#847,#662,#2089,.T.);
#2091=ORIENTED_EDGE('',*,*,#2090,.F.);
#2092=ORIENTED_EDGE('',*,*,#1789,.F.);
#2093=EDGE_LOOP('',(#2083,#2084,#2091,#2092));
#2094=FACE_BOUND('',#2093,.T.);
#2095=ADVANCED_FACE('F1319',(#2094),#2082,.T.);
#2096=CARTESIAN_POINT('',(0.,10.5,81.));
#2097=DIRECTION('',(-1.,0.,0.));
#2098=DIRECTION('',(0.,0.,1.));
#2099=AXIS2_PLACEMENT_3D('',#2096,#2097,#2098);
#2100=CYLINDRICAL_SURFACE('',#2099,1.5);
#2101=ORIENTED_EDGE('',*,*,#2090,.T.);
#2102=ORIENTED_EDGE('',*,*,#663,.F.);
#2103=CARTESIAN_POINT('',(14.25,10.5,81.));
#2104=DIRECTION('',(-1.,0.,0.));
#2105=DIRECTION('',(0.,0.,1.));
#2106=AXIS2_PLACEMENT_3D('',#2103,#2104,#2105);
#2107=CIRCLE('',#2106,1.5);
#2108=EDGE_CURVE('E818',#816,#654,#2107,.T.);
#2109=ORIENTED_EDGE('',*,*,#2108,.F.);
#2110=ORIENTED_EDGE('',*,*,#854,.F.);
#2111=EDGE_LOOP('',(#2101,#2102,#2109,#2110));
#2112=FACE_BOUND('',#2111,.T.);
#2113=ADVANCED_FACE('F1311',(#2112),#2100,.T.);
#2114=CARTESIAN_POINT('',(11.25,14.,81.));
#2115=DIRECTION('',(0.,-1.,0.));
#2116=DIRECTION('',(0.,0.,-1.));
#2117=AXIS2_PLACEMENT_3D('',#2114,#2115,#2116);
#2118=CYLINDRICAL_SURFACE('',#2117,1.5);
#2119=ORIENTED_EDGE('',*,*,#1372,.F.);
#2120=ORIENTED_EDGE('',*,*,#825,.F.);
#2121=CARTESIAN_POINT('',(11.25,13.5,81.));
#2122=DIRECTION('',(0.,-1.,0.));
#2123=DIRECTION('',(0.,0.,-1.));
#2124=AXIS2_PLACEMENT_3D('',#2121,#2122,#2123);
#2125=CIRCLE('',#2124,1.5);
#2126=EDGE_CURVE('E815',#1265,#814,#2125,.T.);
#2127=ORIENTED_EDGE('',*,*,#2126,.F.);
#2128=ORIENTED_EDGE('',*,*,#1266,.F.);
#2129=EDGE_LOOP('',(#2119,#2120,#2127,#2128));
#2130=FACE_BOUND('',#2129,.T.);
#2131=ADVANCED_FACE('F1303',(#2130),#2118,.T.);
#2132=CARTESIAN_POINT('',(14.25,13.5,81.));
#2133=DIRECTION('',(0.,0.,-1.));
#2134=DIRECTION('',(-1.,0.,0.));
#2135=AXIS2_PLACEMENT_3D('',#2132,#2133,#2134);
#2136=TOROIDAL_SURFACE('',#2135,3.,1.5);
#2137=ORIENTED_EDGE('',*,*,#817,.T.);
#2138=ORIENTED_EDGE('',*,*,#2108,.T.);
#2139=CARTESIAN_POINT('',(14.25,13.5,81.));
#2140=DIRECTION('',(0.,0.,-1.));
#2141=DIRECTION('',(-1.,0.,0.));
#2142=AXIS2_PLACEMENT_3D('',#2139,#2140,#2141);
#2143=CIRCLE('',#2142,1.5);
#2144=EDGE_CURVE('E812',#1265,#654,#2143,.F.);
#2145=ORIENTED_EDGE('',*,*,#2144,.F.);
#2146=ORIENTED_EDGE('',*,*,#2126,.T.);
#2147=EDGE_LOOP('',(#2137,#2138,#2145,#2146));
#2148=FACE_BOUND('',#2147,.T.);
#2149=ADVANCED_FACE('F1295',(#2148),#2136,.T.);
#2150=CARTESIAN_POINT('',(-41.,10.5,0.));
#2151=DIRECTION('',(0.,0.,-1.));
#2152=DIRECTION('',(-1.,0.,0.));
#2153=AXIS2_PLACEMENT_3D('',#2150,#2151,#2152);
#2154=CYLINDRICAL_SURFACE('',#2153,1.5);
#2155=ORIENTED_EDGE('',*,*,#613,.F.);
#2156=CARTESIAN_POINT('',(-41.,10.5,45.95));
#2157=DIRECTION('',(0.,0.,-1.));
#2158=DIRECTION('',(-1.,0.,0.));
#2159=AXIS2_PLACEMENT_3D('',#2156,#2157,#2158);
#2160=CIRCLE('',#2159,1.5);
#2161=EDGE_CURVE('E834',#604,#789,#2160,.F.);
#2162=ORIENTED_EDGE('',*,*,#2161,.T.);
#2163=ORIENTED_EDGE('',*,*,#790,.F.);
#2164=CARTESIAN_POINT('',(-41.,10.5,72.5));
#2165=DIRECTION('',(0.,0.,1.));
#2166=DIRECTION('',(1.,0.,0.));
#2167=AXIS2_PLACEMENT_3D('',#2164,#2165,#2166);
#2168=CIRCLE('',#2167,1.5);
#2169=EDGE_CURVE('E809',#612,#781,#2168,.T.);
#2170=ORIENTED_EDGE('',*,*,#2169,.F.);
#2171=EDGE_LOOP('',(#2155,#2162,#2163,#2170));
#2172=FACE_BOUND('',#2171,.T.);
#2173=ADVANCED_FACE('F1287',(#2172),#2154,.T.);
#2174=CARTESIAN_POINT('',(14.25,13.5,82.5));
#2175=DIRECTION('',(0.,0.,-1.));
#2176=DIRECTION('',(-1.,0.,0.));
#2177=AXIS2_PLACEMENT_3D('',#2174,#2175,#2176);
#2178=CYLINDRICAL_SURFACE('',#2177,1.5);
#2179=ORIENTED_EDGE('',*,*,#2144,.T.);
#2180=ORIENTED_EDGE('',*,*,#655,.F.);
#2181=CARTESIAN_POINT('',(14.25,13.5,71.5));
#2182=DIRECTION('',(0.,0.,1.));
#2183=DIRECTION('',(1.,0.,0.));
#2184=AXIS2_PLACEMENT_3D('',#2181,#2182,#2183);
#2185=CIRCLE('',#2184,1.5);
#2186=EDGE_CURVE('E806',#1273,#646,#2185,.T.);
#2187=ORIENTED_EDGE('',*,*,#2186,.F.);
#2188=ORIENTED_EDGE('',*,*,#1274,.F.);
#2189=EDGE_LOOP('',(#2179,#2180,#2187,#2188));
#2190=FACE_BOUND('',#2189,.T.);
#2191=ADVANCED_FACE('F1279',(#2190),#2178,.F.);
#2192=CARTESIAN_POINT('',(-32.5,10.5,72.5));
#2193=DIRECTION('',(0.,1.,0.));
#2194=DIRECTION('',(0.,0.,1.));
#2195=AXIS2_PLACEMENT_3D('',#2192,#2193,#2194);
#2196=TOROIDAL_SURFACE('',#2195,8.5,1.5);
#2197=ORIENTED_EDGE('',*,*,#2169,.T.);
#2198=ORIENTED_EDGE('',*,*,#1807,.F.);
#2199=CARTESIAN_POINT('',(-32.5,10.5,81.));
#2200=DIRECTION('',(1.,0.,0.));
#2201=DIRECTION('',(0.,0.,-1.));
#2202=AXIS2_PLACEMENT_3D('',#2199,#2200,#2201);
#2203=CIRCLE('',#2202,1.5);
#2204=EDGE_CURVE('E803',#621,#712,#2203,.T.);
#2205=ORIENTED_EDGE('',*,*,#2204,.F.);
#2206=ORIENTED_EDGE('',*,*,#622,.F.);
#2207=EDGE_LOOP('',(#2197,#2198,#2205,#2206));
#2208=FACE_BOUND('',#2207,.T.);
#2209=ADVANCED_FACE('F1271',(#2208),#2196,.T.);
#2210=CARTESIAN_POINT('',(0.,13.5,71.5));
#2211=DIRECTION('',(0.,1.,0.));
#2212=DIRECTION('',(0.,0.,1.));
#2213=AXIS2_PLACEMENT_3D('',#2210,#2211,#2212);
#2214=TOROIDAL_SURFACE('',#2213,14.25,1.5);
#2215=ORIENTED_EDGE('',*,*,#2186,.T.);
#2216=ORIENTED_EDGE('',*,*,#647,.F.);
#2217=CARTESIAN_POINT('',(-14.25,13.5,71.5));
#2218=DIRECTION('',(0.,0.,-1.));
#2219=DIRECTION('',(-1.,0.,0.));
#2220=AXIS2_PLACEMENT_3D('',#2217,#2218,#2219);
#2221=CIRCLE('',#2220,1.5);
#2222=EDGE_CURVE('E800',#1297,#637,#2221,.T.);
#2223=ORIENTED_EDGE('',*,*,#2222,.F.);
#2224=ORIENTED_EDGE('',*,*,#1298,.F.);
#2225=EDGE_LOOP('',(#2215,#2216,#2223,#2224));
#2226=FACE_BOUND('',#2225,.T.);
#2227=ADVANCED_FACE('F1263',(#2226),#2214,.F.);
#2228=CARTESIAN_POINT('',(0.,10.5,81.));
#2229=DIRECTION('',(-1.,0.,0.));
#2230=DIRECTION('',(0.,0.,1.));
#2231=AXIS2_PLACEMENT_3D('',#2228,#2229,#2230);
#2232=CYLINDRICAL_SURFACE('',#2231,1.5);
#2233=ORIENTED_EDGE('',*,*,#2204,.T.);
#2234=ORIENTED_EDGE('',*,*,#713,.F.);
#2235=CARTESIAN_POINT('',(-14.25,10.5,81.));
#2236=DIRECTION('',(1.,0.,0.));
#2237=DIRECTION('',(0.,0.,-1.));
#2238=AXIS2_PLACEMENT_3D('',#2235,#2236,#2237);
#2239=CIRCLE('',#2238,1.5);
#2240=EDGE_CURVE('E797',#629,#704,#2239,.T.);
#2241=ORIENTED_EDGE('',*,*,#2240,.F.);
#2242=ORIENTED_EDGE('',*,*,#630,.F.);
#2243=EDGE_LOOP('',(#2233,#2234,#2241,#2242));
#2244=FACE_BOUND('',#2243,.T.);
#2245=ADVANCED_FACE('F1255',(#2244),#2232,.T.);
#2246=CARTESIAN_POINT('',(-14.25,13.5,71.5));
#2247=DIRECTION('',(0.,0.,1.));
#2248=DIRECTION('',(1.,0.,0.));
#2249=AXIS2_PLACEMENT_3D('',#2246,#2247,#2248);
#2250=CYLINDRICAL_SURFACE('',#2249,1.5);
#2251=ORIENTED_EDGE('',*,*,#2222,.T.);
#2252=ORIENTED_EDGE('',*,*,#638,.F.);
#2253=CARTESIAN_POINT('',(-14.25,13.5,81.));
#2254=DIRECTION('',(0.,0.,-1.));
#2255=DIRECTION('',(-1.,0.,0.));
#2256=AXIS2_PLACEMENT_3D('',#2253,#2254,#2255);
#2257=CIRCLE('',#2256,1.5);
#2258=EDGE_CURVE('E793',#1328,#629,#2257,.T.);
#2259=ORIENTED_EDGE('',*,*,#2258,.F.);
#2260=ORIENTED_EDGE('',*,*,#1329,.F.);
#2261=EDGE_LOOP('',(#2251,#2252,#2259,#2260));
#2262=FACE_BOUND('',#2261,.T.);
#2263=ADVANCED_FACE('F1247',(#2262),#2250,.F.);
#2264=CARTESIAN_POINT('',(-14.25,13.5,81.));
#2265=DIRECTION('',(0.,0.,-1.));
#2266=DIRECTION('',(-1.,0.,0.));
#2267=AXIS2_PLACEMENT_3D('',#2264,#2265,#2266);
#2268=TOROIDAL_SURFACE('',#2267,3.,1.5);
#2269=ORIENTED_EDGE('',*,*,#2240,.T.);
#2270=ORIENTED_EDGE('',*,*,#705,.T.);
#2271=CARTESIAN_POINT('',(-11.25,13.5,81.));
#2272=DIRECTION('',(0.,-1.,0.));
#2273=DIRECTION('',(0.,0.,-1.));
#2274=AXIS2_PLACEMENT_3D('',#2271,#2272,#2273);
#2275=CIRCLE('',#2274,1.5);
#2276=EDGE_CURVE('E791',#1328,#695,#2275,.F.);
#2277=ORIENTED_EDGE('',*,*,#2276,.F.);
#2278=ORIENTED_EDGE('',*,*,#2258,.T.);
#2279=EDGE_LOOP('',(#2269,#2270,#2277,#2278));
#2280=FACE_BOUND('',#2279,.T.);
#2281=ADVANCED_FACE('F1239',(#2280),#2268,.T.);
#2282=CARTESIAN_POINT('',(-11.25,12.,81.));
#2283=DIRECTION('',(0.,-1.,0.));
#2284=DIRECTION('',(0.,0.,-1.));
#2285=AXIS2_PLACEMENT_3D('',#2282,#2283,#2284);
#2286=CYLINDRICAL_SURFACE('',#2285,1.5);
#2287=ORIENTED_EDGE('',*,*,#1360,.F.);
#2288=ORIENTED_EDGE('',*,*,#1337,.F.);
#2289=ORIENTED_EDGE('',*,*,#2276,.T.);
#2290=ORIENTED_EDGE('',*,*,#696,.F.);
#2291=EDGE_LOOP('',(#2287,#2288,#2289,#2290));
#2292=FACE_BOUND('',#2291,.T.);
#2293=ADVANCED_FACE('F1233',(#2292),#2286,.T.);
#2294=CARTESIAN_POINT('',(44.45,25.3490095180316,-42.95));
#2295=DIRECTION('',(-1.,0.,0.));
#2296=DIRECTION('',(0.,0.,1.));
#2297=AXIS2_PLACEMENT_3D('',#2294,#2295,#2296);
#2298=CYLINDRICAL_SURFACE('',#2297,1.5);
#2299=ORIENTED_EDGE('',*,*,#160,.F.);
#2300=ORIENTED_EDGE('',*,*,#1117,.F.);
#2301=ORIENTED_EDGE('',*,*,#41,.F.);
#2302=ORIENTED_EDGE('',*,*,#1133,.F.);
#2303=EDGE_LOOP('',(#2299,#2300,#2301,#2302));
#2304=FACE_BOUND('',#2303,.T.);
#2305=ADVANCED_FACE('F971',(#2304),#2298,.T.);
#2306=CARTESIAN_POINT('',(44.45,25.3490095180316,42.95));
#2307=DIRECTION('',(-1.,0.,0.));
#2308=DIRECTION('',(0.,0.,1.));
#2309=AXIS2_PLACEMENT_3D('',#2306,#2307,#2308);
#2310=CYLINDRICAL_SURFACE('',#2309,1.5);
#2311=ORIENTED_EDGE('',*,*,#194,.F.);
#2312=ORIENTED_EDGE('',*,*,#1172,.F.);
#2313=ORIENTED_EDGE('',*,*,#74,.F.);
#2314=ORIENTED_EDGE('',*,*,#1067,.F.);
#2315=EDGE_LOOP('',(#2311,#2312,#2313,#2314));
#2316=FACE_BOUND('',#2315,.T.);
#2317=ADVANCED_FACE('F875',(#2316),#2310,.T.);
#2318=CARTESIAN_POINT('',(-41.,10.5,45.95));
#2319=DIRECTION('',(0.,0.,-1.));
#2320=DIRECTION('',(-1.,0.,0.));
#2321=AXIS2_PLACEMENT_3D('',#2318,#2319,#2320);
#2322=TOROIDAL_SURFACE('',#2321,3.,1.5);
#2323=ORIENTED_EDGE('',*,*,#803,.F.);
#2324=ORIENTED_EDGE('',*,*,#2161,.F.);
#2325=CARTESIAN_POINT('',(-41.,13.5,45.95));
#2326=DIRECTION('',(-1.,0.,0.));
#2327=DIRECTION('',(0.,0.,1.));
#2328=AXIS2_PLACEMENT_3D('',#2325,#2326,#2327);
#2329=CIRCLE('',#2328,1.5);
#2330=EDGE_CURVE('E794',#1049,#604,#2329,.T.);
#2331=ORIENTED_EDGE('',*,*,#2330,.F.);
#2332=ORIENTED_EDGE('',*,*,#1076,.F.);
#2333=ORIENTED_EDGE('',*,*,#982,.F.);
#2334=EDGE_LOOP('',(#2323,#2324,#2331,#2332,#2333));
#2335=FACE_BOUND('',#2334,.T.);
#2336=ADVANCED_FACE('F880',(#2335),#2322,.F.);
#2337=CARTESIAN_POINT('',(0.,13.5,45.95));
#2338=DIRECTION('',(-1.,0.,0.));
#2339=DIRECTION('',(0.,0.,1.));
#2340=AXIS2_PLACEMENT_3D('',#2337,#2338,#2339);
#2341=CYLINDRICAL_SURFACE('',#2340,1.5);
#2342=ORIENTED_EDGE('',*,*,#2330,.T.);
#2343=ORIENTED_EDGE('',*,*,#605,.F.);
#2344=CARTESIAN_POINT('',(41.,13.5,45.95));
#2345=DIRECTION('',(-1.,0.,0.));
#2346=DIRECTION('',(0.,0.,1.));
#2347=AXIS2_PLACEMENT_3D('',#2344,#2345,#2346);
#2348=CIRCLE('',#2347,1.5);
#2349=EDGE_CURVE('E937',#1051,#596,#2348,.T.);
#2350=ORIENTED_EDGE('',*,*,#2349,.F.);
#2351=ORIENTED_EDGE('',*,*,#1052,.F.);
#2352=EDGE_LOOP('',(#2342,#2343,#2350,#2351));
#2353=FACE_BOUND('',#2352,.T.);
#2354=ADVANCED_FACE('F873',(#2353),#2341,.F.);
#2355=CARTESIAN_POINT('',(41.,10.5,45.95));
#2356=DIRECTION('',(0.,0.,-1.));
#2357=DIRECTION('',(-1.,0.,0.));
#2358=AXIS2_PLACEMENT_3D('',#2355,#2356,#2357);
#2359=TOROIDAL_SURFACE('',#2358,3.,1.5);
#2360=ORIENTED_EDGE('',*,*,#2349,.T.);
#2361=ORIENTED_EDGE('',*,*,#2065,.F.);
#2362=ORIENTED_EDGE('',*,*,#916,.F.);
#2363=ORIENTED_EDGE('',*,*,#1013,.F.);
#2364=ORIENTED_EDGE('',*,*,#1059,.F.);
#2365=EDGE_LOOP('',(#2360,#2361,#2362,#2363,#2364));
#2366=FACE_BOUND('',#2365,.T.);
#2367=ADVANCED_FACE('F868',(#2366),#2359,.F.);
#2368=CARTESIAN_POINT('',(-41.,10.5,-45.95));
#2369=DIRECTION('',(0.,0.,1.));
#2370=DIRECTION('',(1.,0.,0.));
#2371=AXIS2_PLACEMENT_3D('',#2368,#2369,#2370);
#2372=TOROIDAL_SURFACE('',#2371,3.,1.5);
#2373=ORIENTED_EDGE('',*,*,#964,.F.);
#2374=ORIENTED_EDGE('',*,*,#1109,.F.);
#2375=CARTESIAN_POINT('',(-41.,13.5,-45.95));
#2376=DIRECTION('',(-1.,0.,0.));
#2377=DIRECTION('',(0.,0.,1.));
#2378=AXIS2_PLACEMENT_3D('',#2375,#2376,#2377);
#2379=CIRCLE('',#2378,1.5);
#2380=EDGE_CURVE('E45',#390,#1101,#2379,.T.);
#2381=ORIENTED_EDGE('',*,*,#2380,.F.);
#2382=ORIENTED_EDGE('',*,*,#1939,.F.);
#2383=ORIENTED_EDGE('',*,*,#759,.F.);
#2384=EDGE_LOOP('',(#2373,#2374,#2381,#2382,#2383));
#2385=FACE_BOUND('',#2384,.T.);
#2386=ADVANCED_FACE('F42',(#2385),#2372,.F.);
#2387=CARTESIAN_POINT('',(44.45,13.5,-45.95));
#2388=DIRECTION('',(-1.,0.,0.));
#2389=DIRECTION('',(0.,0.,1.));
#2390=AXIS2_PLACEMENT_3D('',#2387,#2388,#2389);
#2391=CYLINDRICAL_SURFACE('',#2390,1.5);
#2392=ORIENTED_EDGE('',*,*,#2380,.T.);
#2393=ORIENTED_EDGE('',*,*,#1102,.F.);
#2394=CARTESIAN_POINT('',(41.,13.5,-45.95));
#2395=DIRECTION('',(-1.,0.,0.));
#2396=DIRECTION('',(0.,0.,1.));
#2397=AXIS2_PLACEMENT_3D('',#2394,#2395,#2396);
#2398=CIRCLE('',#2397,1.5);
#2399=EDGE_CURVE('E428',#398,#1093,#2398,.T.);
#2400=ORIENTED_EDGE('',*,*,#2399,.F.);
#2401=ORIENTED_EDGE('',*,*,#399,.F.);
#2402=EDGE_LOOP('',(#2392,#2393,#2400,#2401));
#2403=FACE_BOUND('',#2402,.T.);
#2404=ADVANCED_FACE('F950',(#2403),#2391,.F.);
#2405=CARTESIAN_POINT('',(41.,10.5,-45.95));
#2406=DIRECTION('',(0.,0.,1.));
#2407=DIRECTION('',(1.,0.,0.));
#2408=AXIS2_PLACEMENT_3D('',#2405,#2406,#2407);
#2409=TOROIDAL_SURFACE('',#2408,3.,1.5);
#2410=ORIENTED_EDGE('',*,*,#893,.F.);
#2411=ORIENTED_EDGE('',*,*,#1825,.F.);
#2412=ORIENTED_EDGE('',*,*,#2399,.T.);
#2413=ORIENTED_EDGE('',*,*,#1094,.F.);
#2414=ORIENTED_EDGE('',*,*,#1031,.F.);
#2415=EDGE_LOOP('',(#2410,#2411,#2412,#2413,#2414));
#2416=FACE_BOUND('',#2415,.T.);
#2417=ADVANCED_FACE('F886',(#2416),#2409,.F.);
#2418=CARTESIAN_POINT('',(-25.45,20.,-38.));
#2419=DIRECTION('',(-1.,0.,0.));
#2420=DIRECTION('',(0.,0.,1.));
#2421=AXIS2_PLACEMENT_3D('',#2418,#2419,#2420);
#2422=CONICAL_SURFACE('',#2421,3.,1.02974425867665);
#2423=CARTESIAN_POINT('',(-23.6474181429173,20.,-38.));
#2424=VERTEX_POINT('',#2423);
#2425=VERTEX_LOOP('',#2424);
#2426=FACE_BOUND('',#2425,.T.);
#2427=CARTESIAN_POINT('',(-25.45,20.,-38.));
#2428=DIRECTION('',(-1.,0.,0.));
#2429=DIRECTION('',(0.,0.,1.));
#2430=AXIS2_PLACEMENT_3D('',#2427,#2428,#2429);
#2431=CIRCLE('',#2430,3.);
#2432=CARTESIAN_POINT('',(-25.45,20.,-35.));
#2433=VERTEX_POINT('',#2432);
#2434=EDGE_CURVE('E419',#2433,#2433,#2431,.T.);
#2435=ORIENTED_EDGE('',*,*,#2434,.T.);
#2436=EDGE_LOOP('',(#2435));
#2437=FACE_BOUND('',#2436,.T.);
#2438=ADVANCED_FACE('F1090',(#2426,#2437),#2422,.F.);
#2439=CARTESIAN_POINT('',(-44.45,20.,-38.));
#2440=DIRECTION('',(-1.,0.,0.));
#2441=DIRECTION('',(0.,0.,1.));
#2442=AXIS2_PLACEMENT_3D('',#2439,#2440,#2441);
#2443=CYLINDRICAL_SURFACE('',#2442,3.);
#2444=ORIENTED_EDGE('',*,*,#2434,.F.);
#2445=EDGE_LOOP('',(#2444));
#2446=FACE_BOUND('',#2445,.T.);
#2447=ORIENTED_EDGE('',*,*,#100,.T.);
#2448=EDGE_LOOP('',(#2447));
#2449=FACE_BOUND('',#2448,.T.);
#2450=ADVANCED_FACE('F409',(#2446,#2449),#2443,.F.);
#2451=CARTESIAN_POINT('',(-25.45,20.,38.));
#2452=DIRECTION('',(-1.,0.,0.));
#2453=DIRECTION('',(0.,0.,1.));
#2454=AXIS2_PLACEMENT_3D('',#2451,#2452,#2453);
#2455=CONICAL_SURFACE('',#2454,3.,1.02974425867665);
#2456=CARTESIAN_POINT('',(-23.6474181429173,20.,38.));
#2457=VERTEX_POINT('',#2456);
#2458=VERTEX_LOOP('',#2457);
#2459=FACE_BOUND('',#2458,.T.);
#2460=CARTESIAN_POINT('',(-25.45,20.,38.));
#2461=DIRECTION('',(-1.,0.,0.));
#2462=DIRECTION('',(0.,0.,1.));
#2463=AXIS2_PLACEMENT_3D('',#2460,#2461,#2462);
#2464=CIRCLE('',#2463,3.);
#2465=CARTESIAN_POINT('',(-25.45,20.,41.));
#2466=VERTEX_POINT('',#2465);
#2467=EDGE_CURVE('E413',#2466,#2466,#2464,.T.);
#2468=ORIENTED_EDGE('',*,*,#2467,.T.);
#2469=EDGE_LOOP('',(#2468));
#2470=FACE_BOUND('',#2469,.T.);
#2471=ADVANCED_FACE('F405',(#2459,#2470),#2455,.F.);
#2472=CARTESIAN_POINT('',(-44.45,20.,38.));
#2473=DIRECTION('',(-1.,0.,0.));
#2474=DIRECTION('',(0.,0.,1.));
#2475=AXIS2_PLACEMENT_3D('',#2472,#2473,#2474);
#2476=CYLINDRICAL_SURFACE('',#2475,3.);
#2477=ORIENTED_EDGE('',*,*,#2467,.F.);
#2478=EDGE_LOOP('',(#2477));
#2479=FACE_BOUND('',#2478,.T.);
#2480=ORIENTED_EDGE('',*,*,#111,.T.);
#2481=EDGE_LOOP('',(#2480));
#2482=FACE_BOUND('',#2481,.T.);
#2483=ADVANCED_FACE('F408',(#2479,#2482),#2476,.F.);
#2484=CARTESIAN_POINT('',(29.95,16.5,-23.75));
#2485=DIRECTION('',(1.,0.,0.));
#2486=DIRECTION('',(0.,0.,-1.));
#2487=AXIS2_PLACEMENT_3D('',#2484,#2485,#2486);
#2488=CYLINDRICAL_SURFACE('',#2487,1.5);
#2489=CARTESIAN_POINT('',(29.95,16.5,-23.75));
#2490=DIRECTION('',(-1.,0.,0.));
#2491=DIRECTION('',(0.,0.,1.));
#2492=AXIS2_PLACEMENT_3D('',#2489,#2490,#2491);
#2493=CIRCLE('',#2492,1.5);
#2494=CARTESIAN_POINT('',(29.95,16.5,-25.25));
#2495=VERTEX_POINT('',#2494);
#2496=EDGE_CURVE('E422',#2495,#2495,#2493,.T.);
#2497=CARTESIAN_POINT('',(29.95,16.5,-25.25));
#2498=CARTESIAN_POINT('',(30.1010416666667,16.5,-25.25));
#2499=CARTESIAN_POINT('',(30.2520833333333,16.5,-25.25));
#2500=CARTESIAN_POINT('',(30.5541666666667,16.5,-25.25));
#2501=CARTESIAN_POINT('',(30.7052083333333,16.5,-25.25));
#2502=CARTESIAN_POINT('',(31.0072916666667,16.5,-25.25));
#2503=CARTESIAN_POINT('',(31.1583333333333,16.5,-25.25));
#2504=CARTESIAN_POINT('',(31.4604166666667,16.5,-25.25));
#2505=CARTESIAN_POINT('',(31.6114583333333,16.5,-25.25));
#2506=CARTESIAN_POINT('',(31.9135416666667,16.5,-25.25));
#2507=CARTESIAN_POINT('',(32.0645833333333,16.5,-25.25));
#2508=CARTESIAN_POINT('',(32.3666666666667,16.5,-25.25));
#2509=CARTESIAN_POINT('',(32.5177083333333,16.5,-25.25));
#2510=CARTESIAN_POINT('',(32.8197916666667,16.5,-25.25));
#2511=CARTESIAN_POINT('',(32.9708333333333,16.5,-25.25));
#2512=CARTESIAN_POINT('',(33.2729166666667,16.5,-25.25));
#2513=CARTESIAN_POINT('',(33.4239583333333,16.5,-25.25));
#2514=CARTESIAN_POINT('',(33.7260416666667,16.5,-25.25));
#2515=CARTESIAN_POINT('',(33.8770833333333,16.5,-25.25));
#2516=CARTESIAN_POINT('',(34.1791666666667,16.5,-25.25));
#2517=CARTESIAN_POINT('',(34.3302083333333,16.5,-25.25));
#2518=CARTESIAN_POINT('',(34.6322916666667,16.5,-25.25));
#2519=CARTESIAN_POINT('',(34.7833333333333,16.5,-25.25));
#2520=CARTESIAN_POINT('',(35.0854166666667,16.5,-25.25));
#2521=CARTESIAN_POINT('',(35.2364583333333,16.5,-25.25));
#2522=CARTESIAN_POINT('',(35.5385416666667,16.5,-25.25));
#2523=CARTESIAN_POINT('',(35.6895833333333,16.5,-25.25));
#2524=CARTESIAN_POINT('',(35.9916666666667,16.5,-25.25));
#2525=CARTESIAN_POINT('',(36.1427083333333,16.5,-25.25));
#2526=CARTESIAN_POINT('',(36.4447916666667,16.5,-25.25));
#2527=CARTESIAN_POINT('',(36.5958333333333,16.5,-25.25));
#2528=CARTESIAN_POINT('',(36.8979166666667,16.5,-25.25));
#2529=CARTESIAN_POINT('',(37.0489583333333,16.5,-25.25));
#2530=CARTESIAN_POINT('',(37.3510416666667,16.5,-25.25));
#2531=CARTESIAN_POINT('',(37.5020833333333,16.5,-25.25));
#2532=CARTESIAN_POINT('',(37.8041666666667,16.5,-25.25));
#2533=CARTESIAN_POINT('',(37.9552083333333,16.5,-25.25));
#2534=CARTESIAN_POINT('',(38.2572916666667,16.5,-25.25));
#2535=CARTESIAN_POINT('',(38.4083333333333,16.5,-25.25));
#2536=CARTESIAN_POINT('',(38.7104166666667,16.5,-25.25));
#2537=CARTESIAN_POINT('',(38.8614583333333,16.5,-25.25));
#2538=CARTESIAN_POINT('',(39.1635416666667,16.5,-25.25));
#2539=CARTESIAN_POINT('',(39.3145833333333,16.5,-25.25));
#2540=CARTESIAN_POINT('',(39.6166666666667,16.5,-25.25));
#2541=CARTESIAN_POINT('',(39.7677083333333,16.5,-25.25));
#2542=CARTESIAN_POINT('',(40.0697916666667,16.5,-25.25));
#2543=CARTESIAN_POINT('',(40.2208333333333,16.5,-25.25));
#2544=CARTESIAN_POINT('',(40.5229166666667,16.5,-25.25));
#2545=CARTESIAN_POINT('',(40.6739583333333,16.5,-25.25));
#2546=CARTESIAN_POINT('',(40.9760416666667,16.5,-25.25));
#2547=CARTESIAN_POINT('',(41.1270833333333,16.5,-25.25));
#2548=CARTESIAN_POINT('',(41.4291666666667,16.5,-25.25));
#2549=CARTESIAN_POINT('',(41.5802083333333,16.5,-25.25));
#2550=CARTESIAN_POINT('',(41.8822916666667,16.5,-25.25));
#2551=CARTESIAN_POINT('',(42.0333333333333,16.5,-25.25));
#2552=CARTESIAN_POINT('',(42.3354166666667,16.5,-25.25));
#2553=CARTESIAN_POINT('',(42.4864583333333,16.5,-25.25));
#2554=CARTESIAN_POINT('',(42.7885416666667,16.5,-25.25));
#2555=CARTESIAN_POINT('',(42.9395833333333,16.5,-25.25));
#2556=CARTESIAN_POINT('',(43.2416666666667,16.5,-25.25));
#2557=CARTESIAN_POINT('',(43.3927083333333,16.5,-25.25));
#2558=CARTESIAN_POINT('',(43.6947916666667,16.5,-25.25));
#2559=CARTESIAN_POINT('',(43.8458333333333,16.5,-25.25));
#2560=CARTESIAN_POINT('',(44.1479166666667,16.5,-25.25));
#2561=CARTESIAN_POINT('',(44.2989583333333,16.5,-25.25));
#2562=CARTESIAN_POINT('',(44.45,16.5,-25.25));
#2563=B_SPLINE_CURVE_WITH_KNOTS('',3,(#2497,#2498,#2499,#2500,#2501,#2502,#2503,#2504,#2505,
#2506,#2507,#2508,#2509,#2510,#2511,#2512,#2513,#2514,#2515,#2516,#2517,#2518,#2519,#2520,#2521,
#2522,#2523,#2524,#2525,#2526,#2527,#2528,#2529,#2530,#2531,#2532,#2533,#2534,#2535,#2536,#2537,
#2538,#2539,#2540,#2541,#2542,#2543,#2544,#2545,#2546,#2547,#2548,#2549,#2550,#2551,#2552,#2553,
#2554,#2555,#2556,#2557,#2558,#2559,#2560,#2561,#2562),.UNSPECIFIED.,.F.,.F.,(4,2,2,2,2,2,2,2,2,
2,2,2,2,2,2,2,2,2,2,2,2,2,2,2,2,2,2,2,2,2,2,2,4),(0.,0.453125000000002,0.906250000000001,
1.359375,1.8125,2.265625,2.71875,3.171875,3.625,4.078125,4.53125,4.984375,5.4375,5.890625,
6.34375,6.796875,7.25000000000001,7.70312500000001,8.15625,8.609375,9.0625,9.515625,
9.96875000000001,10.421875,10.875,11.328125,11.78125,12.234375,12.6875,13.140625,13.59375,
14.046875,14.5),.UNSPECIFIED.);
#2564=EDGE_CURVE('BSEAM1099',#2495,#251,#2563,.T.);
#2565=ORIENTED_EDGE('',*,*,#2496,.T.);
#2566=ORIENTED_EDGE('',*,*,#252,.F.);
#2567=ORIENTED_EDGE('',*,*,#2564,.T.);
#2568=ORIENTED_EDGE('',*,*,#2564,.F.);
#2569=EDGE_LOOP('',(#2565,#2567,#2566,#2568));
#2570=FACE_BOUND('',#2569,.T.);
#2571=ADVANCED_FACE('F1099',(#2570),#2488,.F.);
#2572=CARTESIAN_POINT('',(29.95,16.5,-23.75));
#2573=DIRECTION('',(1.,0.,0.));
#2574=DIRECTION('',(0.,0.,1.));
#2575=AXIS2_PLACEMENT_3D('',#2572,#2573,#2574);
#2576=PLANE('',#2575);
#2577=ORIENTED_EDGE('',*,*,#2496,.F.);
#2578=EDGE_LOOP('',(#2577));
#2579=FACE_BOUND('',#2578,.T.);
#2580=ADVANCED_FACE('F1102',(#2579),#2576,.T.);
#2581=CARTESIAN_POINT('',(-29.95,16.5,-23.75));
#2582=DIRECTION('',(-1.,0.,0.));
#2583=DIRECTION('',(0.,0.,1.));
#2584=AXIS2_PLACEMENT_3D('',#2581,#2582,#2583);
#2585=CYLINDRICAL_SURFACE('',#2584,1.5);
#2586=CARTESIAN_POINT('',(-29.95,16.5,-23.75));
#2587=DIRECTION('',(-1.,0.,0.));
#2588=DIRECTION('',(0.,0.,1.));
#2589=AXIS2_PLACEMENT_3D('',#2586,#2587,#2588);
#2590=CIRCLE('',#2589,1.5);
#2591=CARTESIAN_POINT('',(-29.95,16.5,-22.25));
#2592=VERTEX_POINT('',#2591);
#2593=EDGE_CURVE('E1131',#2592,#2592,#2590,.T.);
#2594=CARTESIAN_POINT('',(-29.95,16.5,-22.25));
#2595=CARTESIAN_POINT('',(-30.1010416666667,16.5,-22.25));
#2596=CARTESIAN_POINT('',(-30.2520833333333,16.5,-22.25));
#2597=CARTESIAN_POINT('',(-30.5541666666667,16.5,-22.25));
#2598=CARTESIAN_POINT('',(-30.7052083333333,16.5,-22.25));
#2599=CARTESIAN_POINT('',(-31.0072916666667,16.5,-22.25));
#2600=CARTESIAN_POINT('',(-31.1583333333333,16.5,-22.25));
#2601=CARTESIAN_POINT('',(-31.4604166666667,16.5,-22.25));
#2602=CARTESIAN_POINT('',(-31.6114583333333,16.5,-22.25));
#2603=CARTESIAN_POINT('',(-31.9135416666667,16.5,-22.25));
#2604=CARTESIAN_POINT('',(-32.0645833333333,16.5,-22.25));
#2605=CARTESIAN_POINT('',(-32.3666666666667,16.5,-22.25));
#2606=CARTESIAN_POINT('',(-32.5177083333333,16.5,-22.25));
#2607=CARTESIAN_POINT('',(-32.8197916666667,16.5,-22.25));
#2608=CARTESIAN_POINT('',(-32.9708333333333,16.5,-22.25));
#2609=CARTESIAN_POINT('',(-33.2729166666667,16.5,-22.25));
#2610=CARTESIAN_POINT('',(-33.4239583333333,16.5,-22.25));
#2611=CARTESIAN_POINT('',(-33.7260416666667,16.5,-22.25));
#2612=CARTESIAN_POINT('',(-33.8770833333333,16.5,-22.25));
#2613=CARTESIAN_POINT('',(-34.1791666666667,16.5,-22.25));
#2614=CARTESIAN_POINT('',(-34.3302083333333,16.5,-22.25));
#2615=CARTESIAN_POINT('',(-34.6322916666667,16.5,-22.25));
#2616=CARTESIAN_POINT('',(-34.7833333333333,16.5,-22.25));
#2617=CARTESIAN_POINT('',(-35.0854166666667,16.5,-22.25));
#2618=CARTESIAN_POINT('',(-35.2364583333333,16.5,-22.25));
#2619=CARTESIAN_POINT('',(-35.5385416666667,16.5,-22.25));
#2620=CARTESIAN_POINT('',(-35.6895833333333,16.5,-22.25));
#2621=CARTESIAN_POINT('',(-35.9916666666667,16.5,-22.25));
#2622=CARTESIAN_POINT('',(-36.1427083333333,16.5,-22.25));
#2623=CARTESIAN_POINT('',(-36.4447916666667,16.5,-22.25));
#2624=CARTESIAN_POINT('',(-36.5958333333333,16.5,-22.25));
#2625=CARTESIAN_POINT('',(-36.8979166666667,16.5,-22.25));
#2626=CARTESIAN_POINT('',(-37.0489583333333,16.5,-22.25));
#2627=CARTESIAN_POINT('',(-37.3510416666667,16.5,-22.25));
#2628=CARTESIAN_POINT('',(-37.5020833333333,16.5,-22.25));
#2629=CARTESIAN_POINT('',(-37.8041666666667,16.5,-22.25));
#2630=CARTESIAN_POINT('',(-37.9552083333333,16.5,-22.25));
#2631=CARTESIAN_POINT('',(-38.2572916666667,16.5,-22.25));
#2632=CARTESIAN_POINT('',(-38.4083333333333,16.5,-22.25));
#2633=CARTESIAN_POINT('',(-38.7104166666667,16.5,-22.25));
#2634=CARTESIAN_POINT('',(-38.8614583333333,16.5,-22.25));
#2635=CARTESIAN_POINT('',(-39.1635416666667,16.5,-22.25));
#2636=CARTESIAN_POINT('',(-39.3145833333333,16.5,-22.25));
#2637=CARTESIAN_POINT('',(-39.6166666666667,16.5,-22.25));
#2638=CARTESIAN_POINT('',(-39.7677083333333,16.5,-22.25));
#2639=CARTESIAN_POINT('',(-40.0697916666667,16.5,-22.25));
#2640=CARTESIAN_POINT('',(-40.2208333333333,16.5,-22.25));
#2641=CARTESIAN_POINT('',(-40.5229166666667,16.5,-22.25));
#2642=CARTESIAN_POINT('',(-40.6739583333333,16.5,-22.25));
#2643=CARTESIAN_POINT('',(-40.9760416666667,16.5,-22.25));
#2644=CARTESIAN_POINT('',(-41.1270833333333,16.5,-22.25));
#2645=CARTESIAN_POINT('',(-41.4291666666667,16.5,-22.25));
#2646=CARTESIAN_POINT('',(-41.5802083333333,16.5,-22.25));
#2647=CARTESIAN_POINT('',(-41.8822916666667,16.5,-22.25));
#2648=CARTESIAN_POINT('',(-42.0333333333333,16.5,-22.25));
#2649=CARTESIAN_POINT('',(-42.3354166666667,16.5,-22.25));
#2650=CARTESIAN_POINT('',(-42.4864583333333,16.5,-22.25));
#2651=CARTESIAN_POINT('',(-42.7885416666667,16.5,-22.25));
#2652=CARTESIAN_POINT('',(-42.9395833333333,16.5,-22.25));
#2653=CARTESIAN_POINT('',(-43.2416666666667,16.5,-22.25));
#2654=CARTESIAN_POINT('',(-43.3927083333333,16.5,-22.25));
#2655=CARTESIAN_POINT('',(-43.6947916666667,16.5,-22.25));
#2656=CARTESIAN_POINT('',(-43.8458333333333,16.5,-22.25));
#2657=CARTESIAN_POINT('',(-44.1479166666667,16.5,-22.25));
#2658=CARTESIAN_POINT('',(-44.2989583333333,16.5,-22.25));
#2659=CARTESIAN_POINT('',(-44.45,16.5,-22.25));
#2660=B_SPLINE_CURVE_WITH_KNOTS('',3,(#2594,#2595,#2596,#2597,#2598,#2599,#2600,#2601,#2602,
#2603,#2604,#2605,#2606,#2607,#2608,#2609,#2610,#2611,#2612,#2613,#2614,#2615,#2616,#2617,#2618,
#2619,#2620,#2621,#2622,#2623,#2624,#2625,#2626,#2627,#2628,#2629,#2630,#2631,#2632,#2633,#2634,
#2635,#2636,#2637,#2638,#2639,#2640,#2641,#2642,#2643,#2644,#2645,#2646,#2647,#2648,#2649,#2650,
#2651,#2652,#2653,#2654,#2655,#2656,#2657,#2658,#2659),.UNSPECIFIED.,.F.,.F.,(4,2,2,2,2,2,2,2,2,
2,2,2,2,2,2,2,2,2,2,2,2,2,2,2,2,2,2,2,2,2,2,2,4),(0.,0.453125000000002,0.906250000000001,
1.359375,1.8125,2.265625,2.71875,3.171875,3.625,4.078125,4.53125,4.984375,5.4375,5.890625,
6.34375,6.796875,7.25,7.703125,8.15625,8.609375,9.0625,9.515625,9.96875,10.421875,10.875,
11.328125,11.78125,12.234375,12.6875,13.140625,13.59375,14.046875,14.5),.UNSPECIFIED.);
#2661=EDGE_CURVE('BSEAM1106',#2592,#121,#2660,.T.);
#2662=ORIENTED_EDGE('',*,*,#2593,.F.);
#2663=ORIENTED_EDGE('',*,*,#122,.T.);
#2664=ORIENTED_EDGE('',*,*,#2661,.T.);
#2665=ORIENTED_EDGE('',*,*,#2661,.F.);
#2666=EDGE_LOOP('',(#2662,#2664,#2663,#2665));
#2667=FACE_BOUND('',#2666,.T.);
#2668=ADVANCED_FACE('F1106',(#2667),#2585,.F.);
#2669=CARTESIAN_POINT('',(-29.95,16.5,-23.75));
#2670=DIRECTION('',(-1.,0.,0.));
#2671=DIRECTION('',(0.,0.,1.));
#2672=AXIS2_PLACEMENT_3D('',#2669,#2670,#2671);
#2673=PLANE('',#2672);
#2674=ORIENTED_EDGE('',*,*,#2593,.T.);
#2675=EDGE_LOOP('',(#2674));
#2676=FACE_BOUND('',#2675,.T.);
#2677=ADVANCED_FACE('F1110',(#2676),#2673,.T.);
#2678=CARTESIAN_POINT('',(-29.95,16.5,23.75));
#2679=DIRECTION('',(-1.,0.,0.));
#2680=DIRECTION('',(0.,0.,1.));
#2681=AXIS2_PLACEMENT_3D('',#2678,#2679,#2680);
#2682=CYLINDRICAL_SURFACE('',#2681,1.5);
#2683=CARTESIAN_POINT('',(-29.95,16.5,23.75));
#2684=DIRECTION('',(1.,0.,0.));
#2685=DIRECTION('',(0.,0.,-1.));
#2686=AXIS2_PLACEMENT_3D('',#2683,#2684,#2685);
#2687=CIRCLE('',#2686,1.5);
#2688=CARTESIAN_POINT('',(-29.95,16.5,25.25));
#2689=VERTEX_POINT('',#2688);
#2690=EDGE_CURVE('E1126',#2689,#2689,#2687,.T.);
#2691=CARTESIAN_POINT('',(-29.95,16.5,25.25));
#2692=CARTESIAN_POINT('',(-30.1010416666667,16.5,25.25));
#2693=CARTESIAN_POINT('',(-30.2520833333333,16.5,25.25));
#2694=CARTESIAN_POINT('',(-30.5541666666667,16.5,25.25));
#2695=CARTESIAN_POINT('',(-30.7052083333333,16.5,25.25));
#2696=CARTESIAN_POINT('',(-31.0072916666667,16.5,25.25));
#2697=CARTESIAN_POINT('',(-31.1583333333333,16.5,25.25));
#2698=CARTESIAN_POINT('',(-31.4604166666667,16.5,25.25));
#2699=CARTESIAN_POINT('',(-31.6114583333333,16.5,25.25));
#2700=CARTESIAN_POINT('',(-31.9135416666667,16.5,25.25));
#2701=CARTESIAN_POINT('',(-32.0645833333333,16.5,25.25));
#2702=CARTESIAN_POINT('',(-32.3666666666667,16.5,25.25));
#2703=CARTESIAN_POINT('',(-32.5177083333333,16.5,25.25));
#2704=CARTESIAN_POINT('',(-32.8197916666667,16.5,25.25));
#2705=CARTESIAN_POINT('',(-32.9708333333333,16.5,25.25));
#2706=CARTESIAN_POINT('',(-33.2729166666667,16.5,25.25));
#2707=CARTESIAN_POINT('',(-33.4239583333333,16.5,25.25));
#2708=CARTESIAN_POINT('',(-33.7260416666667,16.5,25.25));
#2709=CARTESIAN_POINT('',(-33.8770833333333,16.5,25.25));
#2710=CARTESIAN_POINT('',(-34.1791666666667,16.5,25.25));
#2711=CARTESIAN_POINT('',(-34.3302083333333,16.5,25.25));
#2712=CARTESIAN_POINT('',(-34.6322916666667,16.5,25.25));
#2713=CARTESIAN_POINT('',(-34.7833333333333,16.5,25.25));
#2714=CARTESIAN_POINT('',(-35.0854166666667,16.5,25.25));
#2715=CARTESIAN_POINT('',(-35.2364583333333,16.5,25.25));
#2716=CARTESIAN_POINT('',(-35.5385416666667,16.5,25.25));
#2717=CARTESIAN_POINT('',(-35.6895833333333,16.5,25.25));
#2718=CARTESIAN_POINT('',(-35.9916666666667,16.5,25.25));
#2719=CARTESIAN_POINT('',(-36.1427083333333,16.5,25.25));
#2720=CARTESIAN_POINT('',(-36.4447916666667,16.5,25.25));
#2721=CARTESIAN_POINT('',(-36.5958333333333,16.5,25.25));
#2722=CARTESIAN_POINT('',(-36.8979166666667,16.5,25.25));
#2723=CARTESIAN_POINT('',(-37.0489583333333,16.5,25.25));
#2724=CARTESIAN_POINT('',(-37.3510416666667,16.5,25.25));
#2725=CARTESIAN_POINT('',(-37.5020833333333,16.5,25.25));
#2726=CARTESIAN_POINT('',(-37.8041666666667,16.5,25.25));
#2727=CARTESIAN_POINT('',(-37.9552083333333,16.5,25.25));
#2728=CARTESIAN_POINT('',(-38.2572916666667,16.5,25.25));
#2729=CARTESIAN_POINT('',(-38.4083333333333,16.5,25.25));
#2730=CARTESIAN_POINT('',(-38.7104166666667,16.5,25.25));
#2731=CARTESIAN_POINT('',(-38.8614583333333,16.5,25.25));
#2732=CARTESIAN_POINT('',(-39.1635416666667,16.5,25.25));
#2733=CARTESIAN_POINT('',(-39.3145833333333,16.5,25.25));
#2734=CARTESIAN_POINT('',(-39.6166666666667,16.5,25.25));
#2735=CARTESIAN_POINT('',(-39.7677083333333,16.5,25.25));
#2736=CARTESIAN_POINT('',(-40.0697916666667,16.5,25.25));
#2737=CARTESIAN_POINT('',(-40.2208333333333,16.5,25.25));
#2738=CARTESIAN_POINT('',(-40.5229166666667,16.5,25.25));
#2739=CARTESIAN_POINT('',(-40.6739583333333,16.5,25.25));
#2740=CARTESIAN_POINT('',(-40.9760416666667,16.5,25.25));
#2741=CARTESIAN_POINT('',(-41.1270833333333,16.5,25.25));
#2742=CARTESIAN_POINT('',(-41.4291666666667,16.5,25.25));
#2743=CARTESIAN_POINT('',(-41.5802083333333,16.5,25.25));
#2744=CARTESIAN_POINT('',(-41.8822916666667,16.5,25.25));
#2745=CARTESIAN_POINT('',(-42.0333333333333,16.5,25.25));
#2746=CARTESIAN_POINT('',(-42.3354166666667,16.5,25.25));
#2747=CARTESIAN_POINT('',(-42.4864583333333,16.5,25.25));
#2748=CARTESIAN_POINT('',(-42.7885416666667,16.5,25.25));
#2749=CARTESIAN_POINT('',(-42.9395833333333,16.5,25.25));
#2750=CARTESIAN_POINT('',(-43.2416666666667,16.5,25.25));
#2751=CARTESIAN_POINT('',(-43.3927083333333,16.5,25.25));
#2752=CARTESIAN_POINT('',(-43.6947916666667,16.5,25.25));
#2753=CARTESIAN_POINT('',(-43.8458333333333,16.5,25.25));
#2754=CARTESIAN_POINT('',(-44.1479166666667,16.5,25.25));
#2755=CARTESIAN_POINT('',(-44.2989583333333,16.5,25.25));
#2756=CARTESIAN_POINT('',(-44.45,16.5,25.25));
#2757=B_SPLINE_CURVE_WITH_KNOTS('',3,(#2691,#2692,#2693,#2694,#2695,#2696,#2697,#2698,#2699,
#2700,#2701,#2702,#2703,#2704,#2705,#2706,#2707,#2708,#2709,#2710,#2711,#2712,#2713,#2714,#2715,
#2716,#2717,#2718,#2719,#2720,#2721,#2722,#2723,#2724,#2725,#2726,#2727,#2728,#2729,#2730,#2731,
#2732,#2733,#2734,#2735,#2736,#2737,#2738,#2739,#2740,#2741,#2742,#2743,#2744,#2745,#2746,#2747,
#2748,#2749,#2750,#2751,#2752,#2753,#2754,#2755,#2756),.UNSPECIFIED.,.F.,.F.,(4,2,2,2,2,2,2,2,2,
2,2,2,2,2,2,2,2,2,2,2,2,2,2,2,2,2,2,2,2,2,2,2,4),(0.,0.453125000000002,0.906250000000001,
1.359375,1.8125,2.265625,2.71875,3.171875,3.625,4.078125,4.53125,4.984375,5.4375,5.890625,
6.34375,6.796875,7.25000000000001,7.70312500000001,8.15625,8.609375,9.0625,9.515625,
9.96875000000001,10.421875,10.875,11.328125,11.78125,12.234375,12.6875,13.140625,13.59375,
14.046875,14.5),.UNSPECIFIED.);
#2758=EDGE_CURVE('BSEAM1114',#2689,#132,#2757,.T.);
#2759=ORIENTED_EDGE('',*,*,#2690,.T.);
#2760=ORIENTED_EDGE('',*,*,#133,.F.);
#2761=ORIENTED_EDGE('',*,*,#2758,.T.);
#2762=ORIENTED_EDGE('',*,*,#2758,.F.);
#2763=EDGE_LOOP('',(#2759,#2761,#2760,#2762));
#2764=FACE_BOUND('',#2763,.T.);
#2765=ADVANCED_FACE('F1114',(#2764),#2682,.F.);
#2766=CARTESIAN_POINT('',(-29.95,16.5,23.75));
#2767=DIRECTION('',(-1.,0.,0.));
#2768=DIRECTION('',(0.,0.,-1.));
#2769=AXIS2_PLACEMENT_3D('',#2766,#2767,#2768);
#2770=PLANE('',#2769);
#2771=ORIENTED_EDGE('',*,*,#2690,.F.);
#2772=EDGE_LOOP('',(#2771));
#2773=FACE_BOUND('',#2772,.T.);
#2774=ADVANCED_FACE('F1118',(#2773),#2770,.T.);
#2775=CLOSED_SHELL('',(#137,#256,#321,#377,#468,#588,#674,#730,#807,#858,#935,#993,#1038,#1080,
#1122,#1144,#1161,#1178,#1202,#1227,#1244,#1284,#1317,#1348,#1378,#1402,#1426,#1444,#1484,#1517,
#1548,#1578,#1599,#1611,#1699,#1708,#1729,#1741,#1759,#1777,#1795,#1813,#1837,#1855,#1873,#1891,
#1909,#1927,#1951,#1969,#1987,#2005,#2023,#2041,#2053,#2077,#2095,#2113,#2131,#2149,#2173,#2191,
#2209,#2227,#2245,#2263,#2281,#2293,#2305,#2317,#2336,#2354,#2367,#2386,#2404,#2417,#2438,#2450,
#2471,#2483,#2571,#2580,#2668,#2677,#2765,#2774));
#2776=MANIFOLD_SOLID_BREP('B2',#2775);
#2777=ADVANCED_BREP_SHAPE_REPRESENTATION('',(#18,#2776),#14);
#2778=SHAPE_DEFINITION_REPRESENTATION(#9,#2777);
ENDSEC;
END-ISO-10303-21;
